VERSION 5.8 ;
BUSBITCHARS "[]" ;
DIVIDERCHAR "/" ;
UNITS
    DATABASE MICRONS 1000 ;
END UNITS

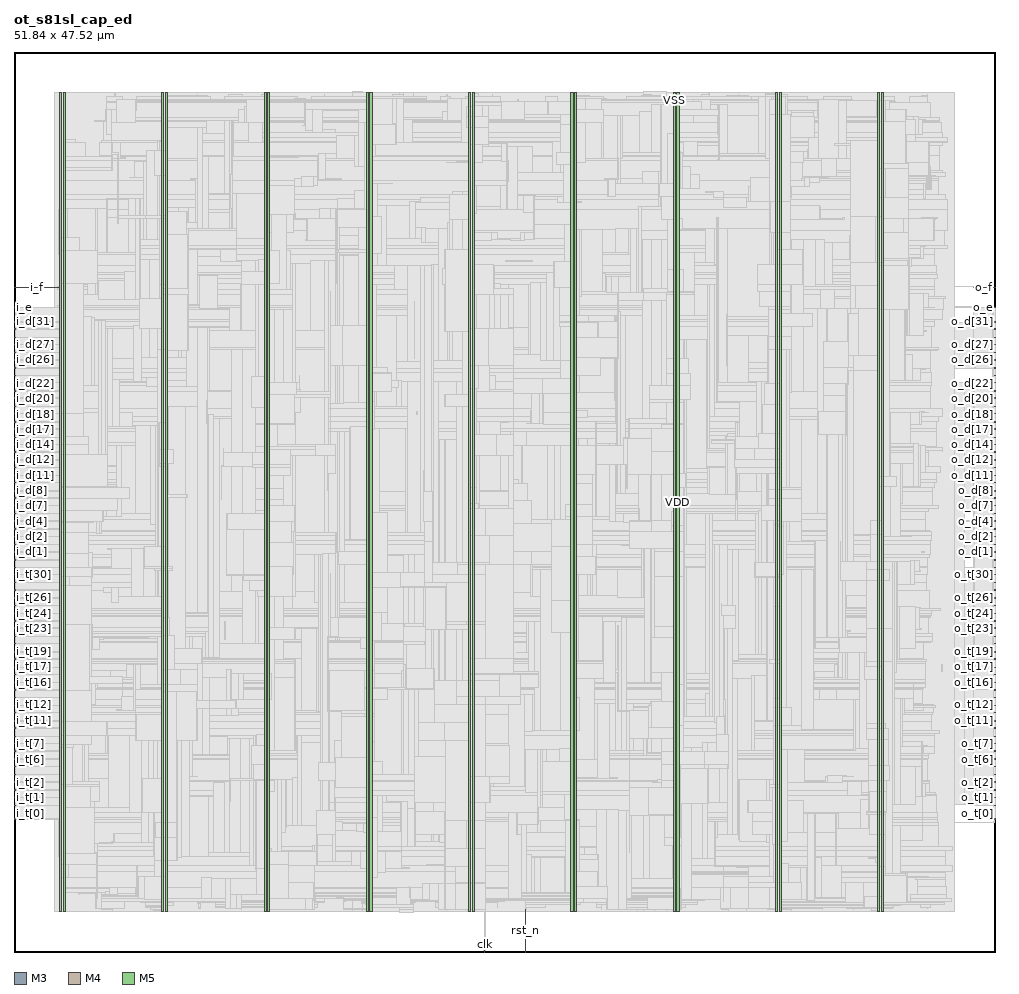
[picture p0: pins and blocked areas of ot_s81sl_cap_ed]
MACRO ot_s81sl_cap_ed
  FOREIGN ot_s81sl_cap_ed 0 0 ;
  CLASS BLOCK ;
  SIZE 51.84 BY 47.52 ;
  PIN clk
    DIRECTION INPUT ;
    USE SIGNAL ;
    PORT
      LAYER M3 ;
        RECT  24.84 0 24.858 0.038 ;
    END
    PORT
      LAYER M3 ;
        RECT  24.84 0.012 24.858 0.125 ;
    END
  END clk
  PIN i_d[0]
    DIRECTION INPUT ;
    USE SIGNAL ;
    PORT
      LAYER M4 ;
        RECT  0 20.688 0.084 20.712 ;
    END
  END i_d[0]
  PIN i_d[10]
    DIRECTION INPUT ;
    USE SIGNAL ;
    PORT
      LAYER M4 ;
        RECT  0 24.768 0.084 24.792 ;
    END
  END i_d[10]
  PIN i_d[11]
    DIRECTION INPUT ;
    USE SIGNAL ;
    PORT
      LAYER M4 ;
        RECT  0 25.152 0.084 25.176 ;
    END
  END i_d[11]
  PIN i_d[12]
    DIRECTION INPUT ;
    USE SIGNAL ;
    PORT
      LAYER M4 ;
        RECT  0 25.584 0.084 25.608 ;
    END
  END i_d[12]
  PIN i_d[13]
    DIRECTION INPUT ;
    USE SIGNAL ;
    PORT
      LAYER M4 ;
        RECT  0 25.968 0.084 25.992 ;
    END
  END i_d[13]
  PIN i_d[14]
    DIRECTION INPUT ;
    USE SIGNAL ;
    PORT
      LAYER M4 ;
        RECT  0 26.4 0.084 26.424 ;
    END
  END i_d[14]
  PIN i_d[15]
    DIRECTION INPUT ;
    USE SIGNAL ;
    PORT
      LAYER M4 ;
        RECT  0 26.784 0.084 26.808 ;
    END
  END i_d[15]
  PIN i_d[16]
    DIRECTION INPUT ;
    USE SIGNAL ;
    PORT
      LAYER M4 ;
        RECT  0 27.168 0.084 27.192 ;
    END
  END i_d[16]
  PIN i_d[17]
    DIRECTION INPUT ;
    USE SIGNAL ;
    PORT
      LAYER M4 ;
        RECT  0 27.6 0.084 27.624 ;
    END
  END i_d[17]
  PIN i_d[18]
    DIRECTION INPUT ;
    USE SIGNAL ;
    PORT
      LAYER M4 ;
        RECT  0 27.984 0.084 28.008 ;
    END
  END i_d[18]
  PIN i_d[19]
    DIRECTION INPUT ;
    USE SIGNAL ;
    PORT
      LAYER M4 ;
        RECT  0 28.416 0.084 28.44 ;
    END
  END i_d[19]
  PIN i_d[1]
    DIRECTION INPUT ;
    USE SIGNAL ;
    PORT
      LAYER M4 ;
        RECT  0 21.12 0.084 21.144 ;
    END
  END i_d[1]
  PIN i_d[20]
    DIRECTION INPUT ;
    USE SIGNAL ;
    PORT
      LAYER M4 ;
        RECT  0 28.8 0.084 28.824 ;
    END
  END i_d[20]
  PIN i_d[21]
    DIRECTION INPUT ;
    USE SIGNAL ;
    PORT
      LAYER M4 ;
        RECT  0 29.232 0.084 29.256 ;
    END
  END i_d[21]
  PIN i_d[22]
    DIRECTION INPUT ;
    USE SIGNAL ;
    PORT
      LAYER M4 ;
        RECT  0 29.616 0.084 29.64 ;
    END
  END i_d[22]
  PIN i_d[23]
    DIRECTION INPUT ;
    USE SIGNAL ;
    PORT
      LAYER M4 ;
        RECT  0 30.048 0.084 30.072 ;
    END
  END i_d[23]
  PIN i_d[24]
    DIRECTION INPUT ;
    USE SIGNAL ;
    PORT
      LAYER M4 ;
        RECT  0 30.432 0.084 30.456 ;
    END
  END i_d[24]
  PIN i_d[25]
    DIRECTION INPUT ;
    USE SIGNAL ;
    PORT
      LAYER M4 ;
        RECT  0 30.816 0.084 30.84 ;
    END
  END i_d[25]
  PIN i_d[26]
    DIRECTION INPUT ;
    USE SIGNAL ;
    PORT
      LAYER M4 ;
        RECT  0 31.248 0.084 31.272 ;
    END
  END i_d[26]
  PIN i_d[27]
    DIRECTION INPUT ;
    USE SIGNAL ;
    PORT
      LAYER M4 ;
        RECT  0 31.632 0.084 31.656 ;
    END
  END i_d[27]
  PIN i_d[28]
    DIRECTION INPUT ;
    USE SIGNAL ;
    PORT
      LAYER M4 ;
        RECT  0 32.064 0.084 32.088 ;
    END
  END i_d[28]
  PIN i_d[29]
    DIRECTION INPUT ;
    USE SIGNAL ;
    PORT
      LAYER M4 ;
        RECT  0 32.448 0.084 32.472 ;
    END
  END i_d[29]
  PIN i_d[2]
    DIRECTION INPUT ;
    USE SIGNAL ;
    PORT
      LAYER M4 ;
        RECT  0 21.504 0.084 21.528 ;
    END
  END i_d[2]
  PIN i_d[30]
    DIRECTION INPUT ;
    USE SIGNAL ;
    PORT
      LAYER M4 ;
        RECT  0 32.88 0.084 32.904 ;
    END
  END i_d[30]
  PIN i_d[31]
    DIRECTION INPUT ;
    USE SIGNAL ;
    PORT
      LAYER M4 ;
        RECT  0 33.264 0.084 33.288 ;
    END
  END i_d[31]
  PIN i_d[3]
    DIRECTION INPUT ;
    USE SIGNAL ;
    PORT
      LAYER M4 ;
        RECT  0 21.936 0.084 21.96 ;
    END
  END i_d[3]
  PIN i_d[4]
    DIRECTION INPUT ;
    USE SIGNAL ;
    PORT
      LAYER M4 ;
        RECT  0 22.32 0.084 22.344 ;
    END
  END i_d[4]
  PIN i_d[5]
    DIRECTION INPUT ;
    USE SIGNAL ;
    PORT
      LAYER M4 ;
        RECT  0 22.752 0.084 22.776 ;
    END
  END i_d[5]
  PIN i_d[6]
    DIRECTION INPUT ;
    USE SIGNAL ;
    PORT
      LAYER M4 ;
        RECT  0 23.136 0.084 23.16 ;
    END
  END i_d[6]
  PIN i_d[7]
    DIRECTION INPUT ;
    USE SIGNAL ;
    PORT
      LAYER M4 ;
        RECT  0 23.568 0.084 23.592 ;
    END
  END i_d[7]
  PIN i_d[8]
    DIRECTION INPUT ;
    USE SIGNAL ;
    PORT
      LAYER M4 ;
        RECT  0 23.952 0.084 23.976 ;
    END
  END i_d[8]
  PIN i_d[9]
    DIRECTION INPUT ;
    USE SIGNAL ;
    PORT
      LAYER M4 ;
        RECT  0 24.336 0.084 24.36 ;
    END
  END i_d[9]
  PIN i_e
    DIRECTION INPUT ;
    USE SIGNAL ;
    PORT
      LAYER M4 ;
        RECT  0 34.032 0.084 34.056 ;
    END
  END i_e
  PIN i_f
    DIRECTION INPUT ;
    USE SIGNAL ;
    PORT
      LAYER M4 ;
        RECT  0 35.088 0.084 35.112 ;
    END
    PORT
      LAYER M4 ;
        RECT  0.06 35.088 2.408 35.112 ;
    END
  END i_f
  PIN i_t[0]
    DIRECTION INPUT ;
    USE SIGNAL ;
    PORT
      LAYER M4 ;
        RECT  0 7.728 0.084 7.752 ;
    END
  END i_t[0]
  PIN i_t[10]
    DIRECTION INPUT ;
    USE SIGNAL ;
    PORT
      LAYER M4 ;
        RECT  0 11.808 0.084 11.832 ;
    END
  END i_t[10]
  PIN i_t[11]
    DIRECTION INPUT ;
    USE SIGNAL ;
    PORT
      LAYER M4 ;
        RECT  0 12.192 0.084 12.216 ;
    END
  END i_t[11]
  PIN i_t[12]
    DIRECTION INPUT ;
    USE SIGNAL ;
    PORT
      LAYER M4 ;
        RECT  0 12.624 0.084 12.648 ;
    END
  END i_t[12]
  PIN i_t[13]
    DIRECTION INPUT ;
    USE SIGNAL ;
    PORT
      LAYER M4 ;
        RECT  0 13.008 0.084 13.032 ;
    END
  END i_t[13]
  PIN i_t[14]
    DIRECTION INPUT ;
    USE SIGNAL ;
    PORT
      LAYER M4 ;
        RECT  0 13.44 0.084 13.464 ;
    END
  END i_t[14]
  PIN i_t[15]
    DIRECTION INPUT ;
    USE SIGNAL ;
    PORT
      LAYER M4 ;
        RECT  0 13.824 0.084 13.848 ;
    END
  END i_t[15]
  PIN i_t[16]
    DIRECTION INPUT ;
    USE SIGNAL ;
    PORT
      LAYER M4 ;
        RECT  0 14.208 0.084 14.232 ;
    END
  END i_t[16]
  PIN i_t[17]
    DIRECTION INPUT ;
    USE SIGNAL ;
    PORT
      LAYER M4 ;
        RECT  0 14.64 0.084 14.664 ;
    END
  END i_t[17]
  PIN i_t[18]
    DIRECTION INPUT ;
    USE SIGNAL ;
    PORT
      LAYER M4 ;
        RECT  0 15.024 0.084 15.048 ;
    END
  END i_t[18]
  PIN i_t[19]
    DIRECTION INPUT ;
    USE SIGNAL ;
    PORT
      LAYER M4 ;
        RECT  0 15.456 0.084 15.48 ;
    END
  END i_t[19]
  PIN i_t[1]
    DIRECTION INPUT ;
    USE SIGNAL ;
    PORT
      LAYER M4 ;
        RECT  0 8.16 0.084 8.184 ;
    END
  END i_t[1]
  PIN i_t[20]
    DIRECTION INPUT ;
    USE SIGNAL ;
    PORT
      LAYER M4 ;
        RECT  0 15.84 0.084 15.864 ;
    END
  END i_t[20]
  PIN i_t[21]
    DIRECTION INPUT ;
    USE SIGNAL ;
    PORT
      LAYER M4 ;
        RECT  0 16.272 0.084 16.296 ;
    END
  END i_t[21]
  PIN i_t[22]
    DIRECTION INPUT ;
    USE SIGNAL ;
    PORT
      LAYER M4 ;
        RECT  0 16.656 0.084 16.68 ;
    END
  END i_t[22]
  PIN i_t[23]
    DIRECTION INPUT ;
    USE SIGNAL ;
    PORT
      LAYER M4 ;
        RECT  0 17.088 0.084 17.112 ;
    END
  END i_t[23]
  PIN i_t[24]
    DIRECTION INPUT ;
    USE SIGNAL ;
    PORT
      LAYER M4 ;
        RECT  0 17.472 0.084 17.496 ;
    END
  END i_t[24]
  PIN i_t[25]
    DIRECTION INPUT ;
    USE SIGNAL ;
    PORT
      LAYER M4 ;
        RECT  0 17.856 0.084 17.88 ;
    END
  END i_t[25]
  PIN i_t[26]
    DIRECTION INPUT ;
    USE SIGNAL ;
    PORT
      LAYER M4 ;
        RECT  0 18.288 0.084 18.312 ;
    END
  END i_t[26]
  PIN i_t[27]
    DIRECTION INPUT ;
    USE SIGNAL ;
    PORT
      LAYER M4 ;
        RECT  0 18.672 0.084 18.696 ;
    END
  END i_t[27]
  PIN i_t[28]
    DIRECTION INPUT ;
    USE SIGNAL ;
    PORT
      LAYER M4 ;
        RECT  0 19.104 0.084 19.128 ;
    END
  END i_t[28]
  PIN i_t[29]
    DIRECTION INPUT ;
    USE SIGNAL ;
    PORT
      LAYER M4 ;
        RECT  0 19.488 0.084 19.512 ;
    END
  END i_t[29]
  PIN i_t[2]
    DIRECTION INPUT ;
    USE SIGNAL ;
    PORT
      LAYER M4 ;
        RECT  0 8.544 0.084 8.568 ;
    END
  END i_t[2]
  PIN i_t[30]
    DIRECTION INPUT ;
    USE SIGNAL ;
    PORT
      LAYER M4 ;
        RECT  0 19.92 0.084 19.944 ;
    END
  END i_t[30]
  PIN i_t[31]
    DIRECTION INPUT ;
    USE SIGNAL ;
    PORT
      LAYER M4 ;
        RECT  0 20.304 0.084 20.328 ;
    END
  END i_t[31]
  PIN i_t[3]
    DIRECTION INPUT ;
    USE SIGNAL ;
    PORT
      LAYER M4 ;
        RECT  0 8.976 0.084 9 ;
    END
  END i_t[3]
  PIN i_t[4]
    DIRECTION INPUT ;
    USE SIGNAL ;
    PORT
      LAYER M4 ;
        RECT  0 9.36 0.084 9.384 ;
    END
  END i_t[4]
  PIN i_t[5]
    DIRECTION INPUT ;
    USE SIGNAL ;
    PORT
      LAYER M4 ;
        RECT  0 9.792 0.084 9.816 ;
    END
  END i_t[5]
  PIN i_t[6]
    DIRECTION INPUT ;
    USE SIGNAL ;
    PORT
      LAYER M4 ;
        RECT  0 10.176 0.084 10.2 ;
    END
  END i_t[6]
  PIN i_t[7]
    DIRECTION INPUT ;
    USE SIGNAL ;
    PORT
      LAYER M4 ;
        RECT  0 10.608 0.084 10.632 ;
    END
  END i_t[7]
  PIN i_t[8]
    DIRECTION INPUT ;
    USE SIGNAL ;
    PORT
      LAYER M4 ;
        RECT  0 10.992 0.084 11.016 ;
    END
  END i_t[8]
  PIN i_t[9]
    DIRECTION INPUT ;
    USE SIGNAL ;
    PORT
      LAYER M4 ;
        RECT  0 11.376 0.084 11.4 ;
    END
  END i_t[9]
  PIN i_v
    DIRECTION INPUT ;
    USE SIGNAL ;
    PORT
      LAYER M4 ;
        RECT  0 7.008 0.084 7.032 ;
    END
  END i_v
  PIN o_d[0]
    DIRECTION OUTPUT ;
    USE SIGNAL ;
    PORT
      LAYER M4 ;
        RECT  51.756 20.688 51.84 20.712 ;
    END
  END o_d[0]
  PIN o_d[10]
    DIRECTION OUTPUT ;
    USE SIGNAL ;
    PORT
      LAYER M4 ;
        RECT  51.756 24.768 51.84 24.792 ;
    END
  END o_d[10]
  PIN o_d[11]
    DIRECTION OUTPUT ;
    USE SIGNAL ;
    PORT
      LAYER M4 ;
        RECT  51.756 25.152 51.84 25.176 ;
    END
  END o_d[11]
  PIN o_d[12]
    DIRECTION OUTPUT ;
    USE SIGNAL ;
    PORT
      LAYER M4 ;
        RECT  51.756 25.584 51.84 25.608 ;
    END
  END o_d[12]
  PIN o_d[13]
    DIRECTION OUTPUT ;
    USE SIGNAL ;
    PORT
      LAYER M4 ;
        RECT  51.756 25.968 51.84 25.992 ;
    END
  END o_d[13]
  PIN o_d[14]
    DIRECTION OUTPUT ;
    USE SIGNAL ;
    PORT
      LAYER M4 ;
        RECT  51.756 26.4 51.84 26.424 ;
    END
  END o_d[14]
  PIN o_d[15]
    DIRECTION OUTPUT ;
    USE SIGNAL ;
    PORT
      LAYER M4 ;
        RECT  51.756 26.784 51.84 26.808 ;
    END
  END o_d[15]
  PIN o_d[16]
    DIRECTION OUTPUT ;
    USE SIGNAL ;
    PORT
      LAYER M4 ;
        RECT  51.756 27.168 51.84 27.192 ;
    END
  END o_d[16]
  PIN o_d[17]
    DIRECTION OUTPUT ;
    USE SIGNAL ;
    PORT
      LAYER M4 ;
        RECT  51.756 27.6 51.84 27.624 ;
    END
  END o_d[17]
  PIN o_d[18]
    DIRECTION OUTPUT ;
    USE SIGNAL ;
    PORT
      LAYER M4 ;
        RECT  51.756 27.984 51.84 28.008 ;
    END
  END o_d[18]
  PIN o_d[19]
    DIRECTION OUTPUT ;
    USE SIGNAL ;
    PORT
      LAYER M4 ;
        RECT  51.756 28.416 51.84 28.44 ;
    END
  END o_d[19]
  PIN o_d[1]
    DIRECTION OUTPUT ;
    USE SIGNAL ;
    PORT
      LAYER M4 ;
        RECT  51.756 21.12 51.84 21.144 ;
    END
  END o_d[1]
  PIN o_d[20]
    DIRECTION OUTPUT ;
    USE SIGNAL ;
    PORT
      LAYER M4 ;
        RECT  51.756 28.8 51.84 28.824 ;
    END
  END o_d[20]
  PIN o_d[21]
    DIRECTION OUTPUT ;
    USE SIGNAL ;
    PORT
      LAYER M4 ;
        RECT  51.756 29.232 51.84 29.256 ;
    END
  END o_d[21]
  PIN o_d[22]
    DIRECTION OUTPUT ;
    USE SIGNAL ;
    PORT
      LAYER M4 ;
        RECT  51.756 29.616 51.84 29.64 ;
    END
  END o_d[22]
  PIN o_d[23]
    DIRECTION OUTPUT ;
    USE SIGNAL ;
    PORT
      LAYER M4 ;
        RECT  51.756 30.048 51.84 30.072 ;
    END
  END o_d[23]
  PIN o_d[24]
    DIRECTION OUTPUT ;
    USE SIGNAL ;
    PORT
      LAYER M4 ;
        RECT  51.756 30.432 51.84 30.456 ;
    END
  END o_d[24]
  PIN o_d[25]
    DIRECTION OUTPUT ;
    USE SIGNAL ;
    PORT
      LAYER M4 ;
        RECT  51.756 30.816 51.84 30.84 ;
    END
  END o_d[25]
  PIN o_d[26]
    DIRECTION OUTPUT ;
    USE SIGNAL ;
    PORT
      LAYER M4 ;
        RECT  51.756 31.248 51.84 31.272 ;
    END
  END o_d[26]
  PIN o_d[27]
    DIRECTION OUTPUT ;
    USE SIGNAL ;
    PORT
      LAYER M4 ;
        RECT  51.756 31.632 51.84 31.656 ;
    END
  END o_d[27]
  PIN o_d[28]
    DIRECTION OUTPUT ;
    USE SIGNAL ;
    PORT
      LAYER M4 ;
        RECT  51.756 32.064 51.84 32.088 ;
    END
  END o_d[28]
  PIN o_d[29]
    DIRECTION OUTPUT ;
    USE SIGNAL ;
    PORT
      LAYER M4 ;
        RECT  51.756 32.448 51.84 32.472 ;
    END
  END o_d[29]
  PIN o_d[2]
    DIRECTION OUTPUT ;
    USE SIGNAL ;
    PORT
      LAYER M4 ;
        RECT  51.756 21.504 51.84 21.528 ;
    END
  END o_d[2]
  PIN o_d[30]
    DIRECTION OUTPUT ;
    USE SIGNAL ;
    PORT
      LAYER M4 ;
        RECT  51.756 32.88 51.84 32.904 ;
    END
  END o_d[30]
  PIN o_d[31]
    DIRECTION OUTPUT ;
    USE SIGNAL ;
    PORT
      LAYER M4 ;
        RECT  51.756 33.264 51.84 33.288 ;
    END
  END o_d[31]
  PIN o_d[3]
    DIRECTION OUTPUT ;
    USE SIGNAL ;
    PORT
      LAYER M4 ;
        RECT  51.756 21.936 51.84 21.96 ;
    END
  END o_d[3]
  PIN o_d[4]
    DIRECTION OUTPUT ;
    USE SIGNAL ;
    PORT
      LAYER M4 ;
        RECT  51.756 22.32 51.84 22.344 ;
    END
  END o_d[4]
  PIN o_d[5]
    DIRECTION OUTPUT ;
    USE SIGNAL ;
    PORT
      LAYER M4 ;
        RECT  51.756 22.752 51.84 22.776 ;
    END
  END o_d[5]
  PIN o_d[6]
    DIRECTION OUTPUT ;
    USE SIGNAL ;
    PORT
      LAYER M4 ;
        RECT  51.756 23.136 51.84 23.16 ;
    END
  END o_d[6]
  PIN o_d[7]
    DIRECTION OUTPUT ;
    USE SIGNAL ;
    PORT
      LAYER M4 ;
        RECT  51.756 23.568 51.84 23.592 ;
    END
  END o_d[7]
  PIN o_d[8]
    DIRECTION OUTPUT ;
    USE SIGNAL ;
    PORT
      LAYER M4 ;
        RECT  51.756 23.952 51.84 23.976 ;
    END
  END o_d[8]
  PIN o_d[9]
    DIRECTION OUTPUT ;
    USE SIGNAL ;
    PORT
      LAYER M4 ;
        RECT  51.756 24.336 51.84 24.36 ;
    END
  END o_d[9]
  PIN o_e
    DIRECTION OUTPUT ;
    USE SIGNAL ;
    PORT
      LAYER M4 ;
        RECT  51.756 34.032 51.84 34.056 ;
    END
  END o_e
  PIN o_f
    DIRECTION OUTPUT ;
    USE SIGNAL ;
    PORT
      LAYER M4 ;
        RECT  51.756 35.088 51.84 35.112 ;
    END
    PORT
      LAYER M4 ;
        RECT  50.677 35.088 51.804 35.112 ;
    END
  END o_f
  PIN o_t[0]
    DIRECTION OUTPUT ;
    USE SIGNAL ;
    PORT
      LAYER M4 ;
        RECT  51.756 7.728 51.84 7.752 ;
    END
  END o_t[0]
  PIN o_t[10]
    DIRECTION OUTPUT ;
    USE SIGNAL ;
    PORT
      LAYER M4 ;
        RECT  51.756 11.808 51.84 11.832 ;
    END
  END o_t[10]
  PIN o_t[11]
    DIRECTION OUTPUT ;
    USE SIGNAL ;
    PORT
      LAYER M4 ;
        RECT  51.756 12.192 51.84 12.216 ;
    END
  END o_t[11]
  PIN o_t[12]
    DIRECTION OUTPUT ;
    USE SIGNAL ;
    PORT
      LAYER M4 ;
        RECT  51.756 12.624 51.84 12.648 ;
    END
  END o_t[12]
  PIN o_t[13]
    DIRECTION OUTPUT ;
    USE SIGNAL ;
    PORT
      LAYER M4 ;
        RECT  51.756 13.008 51.84 13.032 ;
    END
  END o_t[13]
  PIN o_t[14]
    DIRECTION OUTPUT ;
    USE SIGNAL ;
    PORT
      LAYER M4 ;
        RECT  51.756 13.44 51.84 13.464 ;
    END
  END o_t[14]
  PIN o_t[15]
    DIRECTION OUTPUT ;
    USE SIGNAL ;
    PORT
      LAYER M4 ;
        RECT  51.756 13.824 51.84 13.848 ;
    END
  END o_t[15]
  PIN o_t[16]
    DIRECTION OUTPUT ;
    USE SIGNAL ;
    PORT
      LAYER M4 ;
        RECT  51.756 14.208 51.84 14.232 ;
    END
  END o_t[16]
  PIN o_t[17]
    DIRECTION OUTPUT ;
    USE SIGNAL ;
    PORT
      LAYER M4 ;
        RECT  51.756 14.64 51.84 14.664 ;
    END
  END o_t[17]
  PIN o_t[18]
    DIRECTION OUTPUT ;
    USE SIGNAL ;
    PORT
      LAYER M4 ;
        RECT  51.756 15.024 51.84 15.048 ;
    END
  END o_t[18]
  PIN o_t[19]
    DIRECTION OUTPUT ;
    USE SIGNAL ;
    PORT
      LAYER M4 ;
        RECT  51.756 15.456 51.84 15.48 ;
    END
  END o_t[19]
  PIN o_t[1]
    DIRECTION OUTPUT ;
    USE SIGNAL ;
    PORT
      LAYER M4 ;
        RECT  51.756 8.16 51.84 8.184 ;
    END
  END o_t[1]
  PIN o_t[20]
    DIRECTION OUTPUT ;
    USE SIGNAL ;
    PORT
      LAYER M4 ;
        RECT  51.756 15.84 51.84 15.864 ;
    END
  END o_t[20]
  PIN o_t[21]
    DIRECTION OUTPUT ;
    USE SIGNAL ;
    PORT
      LAYER M4 ;
        RECT  51.756 16.272 51.84 16.296 ;
    END
  END o_t[21]
  PIN o_t[22]
    DIRECTION OUTPUT ;
    USE SIGNAL ;
    PORT
      LAYER M4 ;
        RECT  51.756 16.656 51.84 16.68 ;
    END
  END o_t[22]
  PIN o_t[23]
    DIRECTION OUTPUT ;
    USE SIGNAL ;
    PORT
      LAYER M4 ;
        RECT  51.756 17.088 51.84 17.112 ;
    END
  END o_t[23]
  PIN o_t[24]
    DIRECTION OUTPUT ;
    USE SIGNAL ;
    PORT
      LAYER M4 ;
        RECT  51.756 17.472 51.84 17.496 ;
    END
  END o_t[24]
  PIN o_t[25]
    DIRECTION OUTPUT ;
    USE SIGNAL ;
    PORT
      LAYER M4 ;
        RECT  51.756 17.856 51.84 17.88 ;
    END
  END o_t[25]
  PIN o_t[26]
    DIRECTION OUTPUT ;
    USE SIGNAL ;
    PORT
      LAYER M4 ;
        RECT  51.756 18.288 51.84 18.312 ;
    END
  END o_t[26]
  PIN o_t[27]
    DIRECTION OUTPUT ;
    USE SIGNAL ;
    PORT
      LAYER M4 ;
        RECT  51.756 18.672 51.84 18.696 ;
    END
  END o_t[27]
  PIN o_t[28]
    DIRECTION OUTPUT ;
    USE SIGNAL ;
    PORT
      LAYER M4 ;
        RECT  51.756 19.104 51.84 19.128 ;
    END
  END o_t[28]
  PIN o_t[29]
    DIRECTION OUTPUT ;
    USE SIGNAL ;
    PORT
      LAYER M4 ;
        RECT  51.756 19.488 51.84 19.512 ;
    END
  END o_t[29]
  PIN o_t[2]
    DIRECTION OUTPUT ;
    USE SIGNAL ;
    PORT
      LAYER M4 ;
        RECT  51.756 8.544 51.84 8.568 ;
    END
  END o_t[2]
  PIN o_t[30]
    DIRECTION OUTPUT ;
    USE SIGNAL ;
    PORT
      LAYER M4 ;
        RECT  51.756 19.92 51.84 19.944 ;
    END
  END o_t[30]
  PIN o_t[31]
    DIRECTION OUTPUT ;
    USE SIGNAL ;
    PORT
      LAYER M4 ;
        RECT  51.756 20.304 51.84 20.328 ;
    END
  END o_t[31]
  PIN o_t[3]
    DIRECTION OUTPUT ;
    USE SIGNAL ;
    PORT
      LAYER M4 ;
        RECT  51.756 8.976 51.84 9 ;
    END
  END o_t[3]
  PIN o_t[4]
    DIRECTION OUTPUT ;
    USE SIGNAL ;
    PORT
      LAYER M4 ;
        RECT  51.756 9.36 51.84 9.384 ;
    END
  END o_t[4]
  PIN o_t[5]
    DIRECTION OUTPUT ;
    USE SIGNAL ;
    PORT
      LAYER M4 ;
        RECT  51.756 9.792 51.84 9.816 ;
    END
  END o_t[5]
  PIN o_t[6]
    DIRECTION OUTPUT ;
    USE SIGNAL ;
    PORT
      LAYER M4 ;
        RECT  51.756 10.176 51.84 10.2 ;
    END
  END o_t[6]
  PIN o_t[7]
    DIRECTION OUTPUT ;
    USE SIGNAL ;
    PORT
      LAYER M4 ;
        RECT  51.756 10.608 51.84 10.632 ;
    END
  END o_t[7]
  PIN o_t[8]
    DIRECTION OUTPUT ;
    USE SIGNAL ;
    PORT
      LAYER M4 ;
        RECT  51.756 10.992 51.84 11.016 ;
    END
  END o_t[8]
  PIN o_t[9]
    DIRECTION OUTPUT ;
    USE SIGNAL ;
    PORT
      LAYER M4 ;
        RECT  51.756 11.376 51.84 11.4 ;
    END
  END o_t[9]
  PIN o_v
    DIRECTION OUTPUT ;
    USE SIGNAL ;
    PORT
      LAYER M4 ;
        RECT  51.756 7.008 51.84 7.032 ;
    END
  END o_v
  PIN rst_n
    DIRECTION INPUT ;
    USE SIGNAL ;
    PORT
      LAYER M3 ;
        RECT  27 0 27.018 0.038 ;
    END
    PORT
      LAYER M3 ;
        RECT  27 0.012 27.018 2.227 ;
    END
  END rst_n
  PIN VDD
    DIRECTION INOUT ;
    USE POWER ;
    PORT
      LAYER M5 ;
        RECT  45.792 2.151 45.912 45.369 ;
        RECT  40.392 2.151 40.512 45.369 ;
        RECT  34.992 2.151 35.112 45.369 ;
        RECT  29.592 2.151 29.712 45.369 ;
        RECT  24.192 2.151 24.312 45.369 ;
        RECT  18.792 2.151 18.912 45.369 ;
        RECT  13.392 2.151 13.512 45.369 ;
        RECT  7.992 2.151 8.112 45.369 ;
        RECT  2.592 2.151 2.712 45.369 ;
    END
  END VDD
  PIN VSS
    DIRECTION INOUT ;
    USE GROUND ;
    PORT
      LAYER M5 ;
        RECT  45.6 2.137 45.72 45.383 ;
        RECT  40.2 2.137 40.32 45.383 ;
        RECT  34.8 2.137 34.92 45.383 ;
        RECT  29.4 2.137 29.52 45.383 ;
        RECT  24 2.137 24.12 45.383 ;
        RECT  18.6 2.137 18.72 45.383 ;
        RECT  13.2 2.137 13.32 45.383 ;
        RECT  7.8 2.137 7.92 45.383 ;
        RECT  2.4 2.137 2.52 45.383 ;
    END
  END VSS
  # OT_OBS_CLOSED layer=M5 d_um=1.536 added=241
  OBS
    LAYER RVTN ;
     RECT  2.16 2.16 49.68 2.295 ;
     RECT  2.16 2.565 49.68 2.835 ;
     RECT  2.16 3.105 49.68 3.375 ;
     RECT  2.16 3.645 49.68 3.915 ;
     RECT  2.16 4.185 49.68 4.455 ;
     RECT  2.16 4.725 49.68 4.995 ;
     RECT  2.16 5.265 49.68 5.535 ;
     RECT  2.16 5.805 49.68 6.075 ;
     RECT  2.16 6.345 49.68 6.615 ;
     RECT  2.16 6.885 49.68 7.155 ;
     RECT  2.16 7.425 49.68 7.695 ;
     RECT  2.16 7.965 49.68 8.235 ;
     RECT  2.16 8.505 49.68 8.775 ;
     RECT  2.16 9.045 49.68 9.315 ;
     RECT  2.16 9.585 49.68 9.855 ;
     RECT  2.16 10.125 49.68 10.395 ;
     RECT  2.16 10.665 49.68 10.935 ;
     RECT  2.16 11.205 49.68 11.475 ;
     RECT  2.16 11.745 49.68 12.015 ;
     RECT  2.16 12.285 49.68 12.555 ;
     RECT  2.16 12.825 49.68 13.095 ;
     RECT  2.16 13.365 49.68 13.635 ;
     RECT  2.16 13.905 49.68 14.175 ;
     RECT  2.16 14.445 49.68 14.715 ;
     RECT  2.16 14.985 49.68 15.255 ;
     RECT  2.16 15.525 49.68 15.795 ;
     RECT  2.16 16.065 49.68 16.335 ;
     RECT  2.16 16.605 49.68 16.875 ;
     RECT  2.16 17.145 49.68 17.415 ;
     RECT  2.16 17.685 49.68 17.955 ;
     RECT  2.16 18.225 49.68 18.495 ;
     RECT  2.16 18.765 49.68 19.035 ;
     RECT  2.16 19.305 49.68 19.575 ;
     RECT  2.16 19.845 49.68 20.115 ;
     RECT  2.16 20.385 49.68 20.655 ;
     RECT  2.16 20.925 49.68 21.195 ;
     RECT  2.16 21.465 49.68 21.735 ;
     RECT  2.16 22.005 49.68 22.275 ;
     RECT  2.16 22.545 49.68 22.815 ;
     RECT  2.16 23.085 49.68 23.355 ;
     RECT  2.16 23.625 49.68 23.895 ;
     RECT  2.16 24.165 49.68 24.435 ;
     RECT  2.16 24.705 49.68 24.975 ;
     RECT  2.16 25.245 49.68 25.515 ;
     RECT  2.16 25.785 49.68 26.055 ;
     RECT  2.16 26.325 49.68 26.595 ;
     RECT  2.16 26.865 49.68 27.135 ;
     RECT  2.16 27.405 49.68 27.675 ;
     RECT  2.16 27.945 49.68 28.215 ;
     RECT  2.16 28.485 49.68 28.755 ;
     RECT  2.16 29.025 49.68 29.295 ;
     RECT  2.16 29.565 49.68 29.835 ;
     RECT  2.16 30.105 49.68 30.375 ;
     RECT  2.16 30.645 49.68 30.915 ;
     RECT  2.16 31.185 49.68 31.455 ;
     RECT  2.16 31.725 49.68 31.995 ;
     RECT  2.16 32.265 49.68 32.535 ;
     RECT  2.16 32.805 49.68 33.075 ;
     RECT  2.16 33.345 49.68 33.615 ;
     RECT  2.16 33.885 49.68 34.155 ;
     RECT  2.16 34.425 49.68 34.695 ;
     RECT  2.16 34.965 49.68 35.235 ;
     RECT  2.16 35.505 49.68 35.775 ;
     RECT  2.16 36.045 49.68 36.315 ;
     RECT  2.16 36.585 49.68 36.855 ;
     RECT  2.16 37.125 49.68 37.395 ;
     RECT  2.16 37.665 49.68 37.935 ;
     RECT  2.16 38.205 49.68 38.475 ;
     RECT  2.16 38.745 49.68 39.015 ;
     RECT  2.16 39.285 49.68 39.555 ;
     RECT  2.16 39.825 49.68 40.095 ;
     RECT  2.16 40.365 49.68 40.635 ;
     RECT  2.16 40.905 49.68 41.175 ;
     RECT  2.16 41.445 49.68 41.715 ;
     RECT  2.16 41.985 49.68 42.255 ;
     RECT  2.16 42.525 49.68 42.795 ;
     RECT  2.16 43.065 49.68 43.335 ;
     RECT  2.16 43.605 49.68 43.875 ;
     RECT  2.16 44.145 49.68 44.415 ;
     RECT  2.16 44.685 49.68 44.955 ;
     RECT  2.16 45.225 49.68 45.36 ;
    LAYER RVTP ;
     RECT  2.16 2.295 49.68 2.565 ;
     RECT  2.16 2.835 49.68 3.105 ;
     RECT  2.16 3.375 49.68 3.645 ;
     RECT  2.16 3.915 49.68 4.185 ;
     RECT  2.16 4.455 49.68 4.725 ;
     RECT  2.16 4.995 49.68 5.265 ;
     RECT  2.16 5.535 49.68 5.805 ;
     RECT  2.16 6.075 49.68 6.345 ;
     RECT  2.16 6.615 49.68 6.885 ;
     RECT  2.16 7.155 49.68 7.425 ;
     RECT  2.16 7.695 49.68 7.965 ;
     RECT  2.16 8.235 49.68 8.505 ;
     RECT  2.16 8.775 49.68 9.045 ;
     RECT  2.16 9.315 49.68 9.585 ;
     RECT  2.16 9.855 49.68 10.125 ;
     RECT  2.16 10.395 49.68 10.665 ;
     RECT  2.16 10.935 49.68 11.205 ;
     RECT  2.16 11.475 49.68 11.745 ;
     RECT  2.16 12.015 49.68 12.285 ;
     RECT  2.16 12.555 49.68 12.825 ;
     RECT  2.16 13.095 49.68 13.365 ;
     RECT  2.16 13.635 49.68 13.905 ;
     RECT  2.16 14.175 49.68 14.445 ;
     RECT  2.16 14.715 49.68 14.985 ;
     RECT  2.16 15.255 49.68 15.525 ;
     RECT  2.16 15.795 49.68 16.065 ;
     RECT  2.16 16.335 49.68 16.605 ;
     RECT  2.16 16.875 49.68 17.145 ;
     RECT  2.16 17.415 49.68 17.685 ;
     RECT  2.16 17.955 49.68 18.225 ;
     RECT  2.16 18.495 49.68 18.765 ;
     RECT  2.16 19.035 49.68 19.305 ;
     RECT  2.16 19.575 49.68 19.845 ;
     RECT  2.16 20.115 49.68 20.385 ;
     RECT  2.16 20.655 49.68 20.925 ;
     RECT  2.16 21.195 49.68 21.465 ;
     RECT  2.16 21.735 49.68 22.005 ;
     RECT  2.16 22.275 49.68 22.545 ;
     RECT  2.16 22.815 49.68 23.085 ;
     RECT  2.16 23.355 49.68 23.625 ;
     RECT  2.16 23.895 49.68 24.165 ;
     RECT  2.16 24.435 49.68 24.705 ;
     RECT  2.16 24.975 49.68 25.245 ;
     RECT  2.16 25.515 49.68 25.785 ;
     RECT  2.16 26.055 49.68 26.325 ;
     RECT  2.16 26.595 49.68 26.865 ;
     RECT  2.16 27.135 49.68 27.405 ;
     RECT  2.16 27.675 49.68 27.945 ;
     RECT  2.16 28.215 49.68 28.485 ;
     RECT  2.16 28.755 49.68 29.025 ;
     RECT  2.16 29.295 49.68 29.565 ;
     RECT  2.16 29.835 49.68 30.105 ;
     RECT  2.16 30.375 49.68 30.645 ;
     RECT  2.16 30.915 49.68 31.185 ;
     RECT  2.16 31.455 49.68 31.725 ;
     RECT  2.16 31.995 49.68 32.265 ;
     RECT  2.16 32.535 49.68 32.805 ;
     RECT  2.16 33.075 49.68 33.345 ;
     RECT  2.16 33.615 49.68 33.885 ;
     RECT  2.16 34.155 49.68 34.425 ;
     RECT  2.16 34.695 49.68 34.965 ;
     RECT  2.16 35.235 49.68 35.505 ;
     RECT  2.16 35.775 49.68 36.045 ;
     RECT  2.16 36.315 49.68 36.585 ;
     RECT  2.16 36.855 49.68 37.125 ;
     RECT  2.16 37.395 49.68 37.665 ;
     RECT  2.16 37.935 49.68 38.205 ;
     RECT  2.16 38.475 49.68 38.745 ;
     RECT  2.16 39.015 49.68 39.285 ;
     RECT  2.16 39.555 49.68 39.825 ;
     RECT  2.16 40.095 49.68 40.365 ;
     RECT  2.16 40.635 49.68 40.905 ;
     RECT  2.16 41.175 49.68 41.445 ;
     RECT  2.16 41.715 49.68 41.985 ;
     RECT  2.16 42.255 49.68 42.525 ;
     RECT  2.16 42.795 49.68 43.065 ;
     RECT  2.16 43.335 49.68 43.605 ;
     RECT  2.16 43.875 49.68 44.145 ;
     RECT  2.16 44.415 49.68 44.685 ;
     RECT  2.16 44.955 49.68 45.225 ;
    LAYER M1 ;
     RECT  2.16 2.151 49.68 45.369 ;
    LAYER M2 ;
     RECT  2.16 2.151 17.851 45.369 ;
     RECT  17.851 2.151 18.383 45.414 ;
     RECT  18.383 2.151 20.335 45.369 ;
     RECT  20.335 2.106 21.119 45.369 ;
     RECT  21.119 2.151 33.223 45.369 ;
     RECT  33.223 2.151 34.475 45.414 ;
     RECT  34.475 2.151 49.68 45.369 ;
     RECT  49.68 7.776 50.207 30.06 ;
     RECT  50.207 7.776 50.675 19.944 ;
     RECT  50.675 7.938 50.711 19.944 ;
     RECT  50.207 20.826 50.711 22.464 ;
     RECT  50.207 23.256 50.711 30.06 ;
     RECT  49.68 30.816 50.711 33.264 ;
     RECT  49.68 34.056 50.711 34.074 ;
     RECT  49.68 35.136 50.711 35.154 ;
     RECT  50.711 7.938 50.747 7.956 ;
     RECT  50.711 16.506 50.747 17.064 ;
     RECT  50.711 19.476 50.747 19.494 ;
     RECT  50.711 21.636 50.747 21.924 ;
     RECT  50.711 25.686 50.747 25.974 ;
     RECT  50.711 28.386 50.747 28.404 ;
     RECT  50.711 30.816 50.747 31.914 ;
     RECT  49.68 6.822 51.755 6.84 ;
     RECT  50.711 10.296 51.755 10.314 ;
     RECT  50.711 14.346 51.755 15.354 ;
     RECT  50.747 21.636 51.755 21.654 ;
     RECT  50.747 25.686 51.755 25.704 ;
     RECT  50.711 26.766 51.755 26.784 ;
     RECT  50.711 29.736 51.755 29.754 ;
     RECT  50.747 30.816 51.755 31.374 ;
     RECT  50.711 32.976 51.755 32.994 ;
    LAYER M3 ;
     RECT  7.815 2.143 7.905 2.191 ;
     RECT  24.015 2.143 24.105 2.191 ;
     RECT  45.615 2.143 45.705 2.191 ;
     RECT  7.38 2.191 7.905 2.227 ;
     RECT  20.34 2.101 20.358 2.227 ;
     RECT  21.096 2.101 21.114 2.227 ;
     RECT  22.824 2.191 22.842 2.227 ;
     RECT  23.94 2.191 24.105 2.227 ;
     RECT  32.904 2.191 32.922 2.227 ;
     RECT  40.215 2.143 40.305 2.227 ;
     RECT  22.824 2.227 23.094 2.251 ;
     RECT  23.94 2.227 24.498 2.251 ;
     RECT  32.328 2.227 32.922 2.251 ;
     RECT  33.804 2.191 33.822 2.251 ;
     RECT  5.184 2.191 5.202 2.263 ;
     RECT  37.728 2.191 37.746 2.263 ;
     RECT  39.78 2.227 40.305 2.263 ;
     RECT  41.04 2.191 41.058 2.263 ;
     RECT  4.608 2.263 5.202 2.299 ;
     RECT  11.988 2.227 12.006 2.299 ;
     RECT  38.664 2.191 38.682 2.299 ;
     RECT  39.78 2.263 41.058 2.299 ;
     RECT  42.696 2.263 42.714 2.299 ;
     RECT  44.316 2.263 44.334 2.299 ;
     RECT  45.288 2.191 45.705 2.299 ;
     RECT  7.2 2.227 7.905 2.335 ;
     RECT  9.756 2.299 9.846 2.335 ;
     RECT  11.16 2.299 12.006 2.335 ;
     RECT  15.84 2.251 15.858 2.335 ;
     RECT  22.428 2.251 24.498 2.335 ;
     RECT  39.78 2.299 42.714 2.335 ;
     RECT  43.956 2.299 46.386 2.335 ;
     RECT  7.02 2.335 7.974 2.371 ;
     RECT  10.656 2.335 12.186 2.371 ;
     RECT  13.215 2.143 13.305 2.371 ;
     RECT  14.184 2.227 14.202 2.371 ;
     RECT  15.732 2.335 15.858 2.371 ;
     RECT  18.615 2.143 18.705 2.371 ;
     RECT  20.34 2.227 21.114 2.371 ;
     RECT  27 2.227 27.054 2.371 ;
     RECT  30.996 2.263 31.014 2.371 ;
     RECT  32.328 2.251 33.822 2.371 ;
     RECT  34.815 2.143 34.905 2.371 ;
     RECT  37.332 2.263 37.746 2.371 ;
     RECT  38.484 2.299 38.682 2.371 ;
     RECT  39.78 2.335 42.93 2.371 ;
     RECT  43.74 2.335 46.386 2.371 ;
     RECT  48.24 2.299 48.258 2.371 ;
     RECT  2.415 2.143 2.505 2.413 ;
     RECT  6.948 2.371 7.974 2.413 ;
     RECT  10.656 2.371 13.305 2.413 ;
     RECT  14.184 2.371 14.994 2.413 ;
     RECT  29.415 2.143 29.505 2.413 ;
     RECT  6.948 2.413 8.097 2.461 ;
     RECT  39.78 2.371 46.458 2.461 ;
     RECT  10.656 2.413 14.994 2.497 ;
     RECT  15.732 2.371 16.038 2.497 ;
     RECT  18.615 2.371 21.114 2.497 ;
     RECT  27 2.371 28.062 2.497 ;
     RECT  29.415 2.413 29.697 2.497 ;
     RECT  39.78 2.461 46.782 2.497 ;
     RECT  47.88 2.371 48.402 2.497 ;
     RECT  27 2.497 28.242 2.533 ;
     RECT  29.088 2.497 29.934 2.533 ;
     RECT  30.78 2.371 31.014 2.533 ;
     RECT  32.148 2.371 35.478 2.533 ;
     RECT  39.78 2.497 49.014 2.533 ;
     RECT  9.72 2.335 9.846 2.569 ;
     RECT  18.576 2.497 21.114 2.569 ;
     RECT  6.948 2.461 8.442 2.605 ;
     RECT  9.684 2.569 9.846 2.605 ;
     RECT  10.656 2.497 16.038 2.605 ;
     RECT  18.36 2.569 21.114 2.605 ;
     RECT  22.248 2.335 24.498 2.605 ;
     RECT  25.524 2.371 25.542 2.605 ;
     RECT  27 2.533 29.934 2.605 ;
     RECT  30.78 2.533 31.266 2.605 ;
     RECT  32.148 2.533 36.09 2.605 ;
     RECT  37.332 2.371 38.79 2.605 ;
     RECT  39.78 2.533 49.122 2.605 ;
     RECT  4.32 2.299 5.85 2.641 ;
     RECT  6.696 2.605 8.442 2.641 ;
     RECT  9.684 2.605 16.398 2.641 ;
     RECT  17.388 2.251 17.406 2.641 ;
     RECT  18.36 2.605 21.222 2.641 ;
     RECT  22.248 2.605 25.542 2.641 ;
     RECT  37.332 2.605 49.122 2.641 ;
     RECT  37.332 2.641 49.482 2.669 ;
     RECT  17.388 2.641 17.478 2.731 ;
     RECT  18.36 2.641 25.902 2.731 ;
     RECT  27 2.605 36.09 2.731 ;
     RECT  17.388 2.731 36.45 2.779 ;
     RECT  37.332 2.669 46.566 2.803 ;
     RECT  47.34 2.669 49.482 2.831 ;
     RECT  4.32 2.641 16.398 2.839 ;
     RECT  17.388 2.779 36.522 2.839 ;
     RECT  4.32 2.839 36.522 2.911 ;
     RECT  4.284 2.911 36.522 3.001 ;
     RECT  37.26 2.803 46.566 3.001 ;
     RECT  47.34 2.831 49.23 3.029 ;
     RECT  3.456 3.037 3.474 3.073 ;
     RECT  4.284 3.001 46.566 3.073 ;
     RECT  3.456 3.073 46.566 3.109 ;
     RECT  2.415 2.413 2.697 3.145 ;
     RECT  3.42 3.109 46.566 3.145 ;
     RECT  2.415 3.145 46.566 3.335 ;
     RECT  2.415 3.335 42.498 3.407 ;
     RECT  47.7 3.029 49.23 3.443 ;
     RECT  47.7 3.443 49.158 3.811 ;
     RECT  43.416 3.335 46.566 3.955 ;
     RECT  47.592 3.811 49.158 3.955 ;
     RECT  32.508 3.407 42.498 4.081 ;
     RECT  32.508 4.081 42.606 4.171 ;
     RECT  32.508 4.171 42.678 4.189 ;
     RECT  43.416 3.955 49.158 4.189 ;
     RECT  2.415 3.407 31.698 4.225 ;
     RECT  32.508 4.189 49.158 4.225 ;
     RECT  2.415 4.225 49.158 4.261 ;
     RECT  2.415 4.261 49.554 4.559 ;
     RECT  2.415 4.559 49.158 5.035 ;
     RECT  2.376 5.035 49.158 5.341 ;
     RECT  2.376 5.341 49.554 5.567 ;
     RECT  2.376 5.567 48.834 6.845 ;
     RECT  2.376 6.845 48.762 7.003 ;
     RECT  51.732 6.817 51.75 7.037 ;
     RECT  2.304 7.003 48.762 7.115 ;
     RECT  2.376 7.115 48.762 7.349 ;
     RECT  50.652 7.723 50.67 7.799 ;
     RECT  50.724 7.933 50.742 8.189 ;
     RECT  2.415 7.349 48.69 8.267 ;
     RECT  44.748 8.267 48.69 8.303 ;
     RECT  44.748 8.303 48.654 8.429 ;
     RECT  2.415 8.267 44.01 8.539 ;
     RECT  2.304 8.539 44.01 9.005 ;
     RECT  2.415 9.005 44.01 9.013 ;
     RECT  44.748 8.429 48.33 9.013 ;
     RECT  2.415 9.013 48.33 9.077 ;
     RECT  50.688 8.539 50.706 9.821 ;
     RECT  2.415 9.077 48.258 10.171 ;
     RECT  2.304 10.171 48.258 10.201 ;
     RECT  51.732 10.171 51.75 10.319 ;
     RECT  2.304 10.201 48.294 10.355 ;
     RECT  2.415 10.355 48.294 10.471 ;
     RECT  0.108 11.227 0.126 11.405 ;
     RECT  2.415 10.471 48.582 11.435 ;
     RECT  38.628 11.435 48.582 11.551 ;
     RECT  38.628 11.551 48.87 11.669 ;
     RECT  2.415 11.435 37.854 11.803 ;
     RECT  2.304 11.803 37.854 12.181 ;
     RECT  38.628 11.669 48.438 12.181 ;
     RECT  2.304 12.181 48.438 12.523 ;
     RECT  2.304 12.523 48.474 12.631 ;
     RECT  2.304 12.631 48.546 12.901 ;
     RECT  2.304 12.901 48.654 13.019 ;
     RECT  43.308 13.019 48.546 13.055 ;
     RECT  43.38 13.055 48.546 13.091 ;
     RECT  43.38 13.091 47.97 13.127 ;
     RECT  2.304 13.019 42.534 13.325 ;
     RECT  0.108 13.435 0.126 13.613 ;
     RECT  2.376 13.325 42.534 13.837 ;
     RECT  50.688 10.561 50.706 13.853 ;
     RECT  2.376 13.837 42.57 13.873 ;
     RECT  43.416 13.127 47.97 13.873 ;
     RECT  2.376 13.873 47.97 13.909 ;
     RECT  2.376 13.909 48.006 13.945 ;
     RECT  2.376 13.945 48.114 14.203 ;
     RECT  2.304 14.203 48.114 14.215 ;
     RECT  2.304 14.215 48.15 14.369 ;
     RECT  2.304 14.369 48.114 14.405 ;
     RECT  48.996 14.791 49.014 15.179 ;
     RECT  2.376 14.405 48.114 15.245 ;
     RECT  2.412 15.245 48.114 15.331 ;
     RECT  51.732 14.203 51.75 15.359 ;
     RECT  2.412 15.331 48.186 15.449 ;
     RECT  2.412 15.449 48.042 15.485 ;
     RECT  50.724 15.151 50.742 15.485 ;
     RECT  50.688 15.835 50.706 16.301 ;
     RECT  2.415 15.485 48.042 16.339 ;
     RECT  2.415 16.339 48.366 16.375 ;
     RECT  2.415 16.375 48.474 16.651 ;
     RECT  2.304 16.651 48.474 16.799 ;
     RECT  2.304 16.799 48.294 16.835 ;
     RECT  2.304 16.835 42.714 16.907 ;
     RECT  2.304 16.907 42.642 17.117 ;
     RECT  50.724 16.501 50.742 17.117 ;
     RECT  43.56 16.835 48.294 17.653 ;
     RECT  2.376 17.117 42.642 17.689 ;
     RECT  43.56 17.653 48.402 17.689 ;
     RECT  2.376 17.689 48.402 17.761 ;
     RECT  2.376 17.761 48.438 17.851 ;
     RECT  2.304 17.851 48.438 18.031 ;
     RECT  2.304 18.031 48.906 18.149 ;
     RECT  2.304 18.149 48.33 19.103 ;
     RECT  50.688 17.467 50.706 19.471 ;
     RECT  50.688 19.471 50.742 19.517 ;
     RECT  2.304 19.103 48.186 19.535 ;
     RECT  2.412 19.535 48.186 19.921 ;
     RECT  0.108 19.819 0.126 19.949 ;
     RECT  50.688 19.517 50.706 19.949 ;
     RECT  2.412 19.921 48.222 20.299 ;
     RECT  50.184 20.191 50.202 20.333 ;
     RECT  2.34 20.299 48.222 20.345 ;
     RECT  2.415 20.345 48.222 20.821 ;
     RECT  2.415 20.821 48.33 21.001 ;
     RECT  50.688 20.683 50.706 21.155 ;
     RECT  2.415 21.001 48.366 21.499 ;
     RECT  51.732 21.499 51.75 21.659 ;
     RECT  2.304 21.499 48.366 21.703 ;
     RECT  2.304 21.703 48.438 21.965 ;
     RECT  50.724 21.901 50.742 21.965 ;
     RECT  2.415 21.965 48.438 22.199 ;
     RECT  2.415 22.199 48.33 22.235 ;
     RECT  50.688 22.315 50.706 22.711 ;
     RECT  50.184 22.711 50.706 22.781 ;
     RECT  2.415 22.235 48.114 22.843 ;
     RECT  2.376 22.843 48.114 23.251 ;
     RECT  2.376 23.251 48.294 23.431 ;
     RECT  2.376 23.431 48.798 23.549 ;
     RECT  2.376 23.549 48.474 23.557 ;
     RECT  2.34 23.557 48.474 24.331 ;
     RECT  2.304 24.331 48.474 24.511 ;
     RECT  2.304 24.511 48.618 24.781 ;
     RECT  2.304 24.781 48.69 24.935 ;
     RECT  50.688 22.781 50.706 25.181 ;
     RECT  2.376 24.935 48.69 25.321 ;
     RECT  2.376 25.321 48.906 25.619 ;
     RECT  51.732 25.579 51.75 25.709 ;
     RECT  50.724 25.951 50.742 25.997 ;
     RECT  0.108 25.963 0.126 26.093 ;
     RECT  2.376 25.619 48.294 26.395 ;
     RECT  2.304 26.395 48.294 26.491 ;
     RECT  49.032 26.401 49.05 26.491 ;
     RECT  2.304 26.491 49.05 26.663 ;
     RECT  2.304 26.663 48.726 26.699 ;
     RECT  51.732 26.761 51.75 26.813 ;
     RECT  2.304 26.699 26.226 26.897 ;
     RECT  2.34 26.897 26.226 27.481 ;
     RECT  27.036 26.699 48.726 27.481 ;
     RECT  2.34 27.481 48.726 27.635 ;
     RECT  2.376 27.635 48.726 28.021 ;
     RECT  2.376 28.021 48.834 28.291 ;
     RECT  50.688 26.395 50.706 28.381 ;
     RECT  50.688 28.381 50.742 28.445 ;
     RECT  2.376 28.291 49.014 28.679 ;
     RECT  50.688 28.445 50.706 29.261 ;
     RECT  2.415 28.679 48.402 29.611 ;
     RECT  2.304 29.611 48.402 29.911 ;
     RECT  2.304 29.911 48.438 30.077 ;
     RECT  50.688 30.037 50.706 30.077 ;
     RECT  2.415 30.077 48.438 30.605 ;
     RECT  2.415 30.605 48.402 30.811 ;
     RECT  51.732 29.611 51.75 30.811 ;
     RECT  51.696 30.811 51.75 31.109 ;
     RECT  0.108 31.147 0.126 31.277 ;
     RECT  51.732 31.109 51.75 31.379 ;
     RECT  50.688 31.621 50.706 31.661 ;
     RECT  2.304 30.811 48.402 31.765 ;
     RECT  2.304 31.765 48.762 31.801 ;
     RECT  2.304 31.801 48.834 31.919 ;
     RECT  50.724 31.891 50.742 32.093 ;
     RECT  50.688 32.431 50.706 32.477 ;
     RECT  51.732 32.875 51.75 32.999 ;
     RECT  2.304 31.919 48.438 33.043 ;
     RECT  2.304 33.043 48.582 33.293 ;
     RECT  50.688 33.241 50.706 33.293 ;
     RECT  2.415 33.293 48.582 33.421 ;
     RECT  2.415 33.421 49.014 33.917 ;
     RECT  43.344 33.917 49.014 33.925 ;
     RECT  2.415 33.917 35.55 34.027 ;
     RECT  50.688 34.027 50.706 34.079 ;
     RECT  2.304 34.027 35.55 34.115 ;
     RECT  43.344 33.925 49.086 34.501 ;
     RECT  43.344 34.501 49.194 34.619 ;
     RECT  2.415 34.115 35.55 34.699 ;
     RECT  36.396 33.917 42.606 34.699 ;
     RECT  2.415 34.699 42.606 35.005 ;
     RECT  43.344 34.619 48.582 35.005 ;
     RECT  2.304 35.005 48.582 35.117 ;
     RECT  2.415 35.117 48.582 35.159 ;
     RECT  50.688 35.083 50.706 35.159 ;
     RECT  3.42 35.159 48.582 35.581 ;
     RECT  3.42 35.581 48.762 35.771 ;
     RECT  2.415 35.159 2.697 35.899 ;
     RECT  3.42 35.771 48.69 35.899 ;
     RECT  2.415 35.899 48.69 36.239 ;
     RECT  2.415 36.239 48.618 36.823 ;
     RECT  2.376 36.823 48.618 37.129 ;
     RECT  2.376 37.129 49.266 37.319 ;
     RECT  2.376 37.319 49.122 38.101 ;
     RECT  2.376 38.101 49.302 39.209 ;
     RECT  2.415 39.209 49.302 39.749 ;
     RECT  2.415 39.749 49.194 40.019 ;
     RECT  2.415 40.019 48.798 40.739 ;
     RECT  41.58 40.739 48.798 40.865 ;
     RECT  41.616 40.865 48.798 40.937 ;
     RECT  43.452 40.937 48.798 40.945 ;
     RECT  43.452 40.945 49.194 41.135 ;
     RECT  43.452 41.135 49.014 41.279 ;
     RECT  2.415 40.739 40.806 41.791 ;
     RECT  41.616 40.937 42.642 41.791 ;
     RECT  2.415 41.791 42.642 42.017 ;
     RECT  4.5 42.017 42.642 42.053 ;
     RECT  36.108 42.053 42.642 42.061 ;
     RECT  43.452 41.279 48.87 42.061 ;
     RECT  36.108 42.061 48.87 42.565 ;
     RECT  36.108 42.565 49.014 42.727 ;
     RECT  2.415 42.017 3.762 42.755 ;
     RECT  4.5 42.053 35.334 42.755 ;
     RECT  13.104 42.755 35.334 42.799 ;
     RECT  36.108 42.727 49.266 42.799 ;
     RECT  4.644 42.755 12.366 42.827 ;
     RECT  2.415 42.755 3.258 42.899 ;
     RECT  13.104 42.799 49.266 42.989 ;
     RECT  13.104 42.989 49.014 43.259 ;
     RECT  13.104 43.259 48.978 43.799 ;
     RECT  4.716 42.827 12.366 43.843 ;
     RECT  13.104 43.799 48.87 43.843 ;
     RECT  4.284 43.843 48.87 43.901 ;
     RECT  4.86 43.901 48.87 44.069 ;
     RECT  4.86 44.069 48.402 44.879 ;
     RECT  4.86 44.879 28.674 44.909 ;
     RECT  4.86 44.909 26.622 44.915 ;
     RECT  27.504 44.909 28.674 44.915 ;
     RECT  45.504 44.879 46.53 44.915 ;
     RECT  6.444 44.915 23.058 44.951 ;
     RECT  29.415 44.879 44.55 44.957 ;
     RECT  45.504 44.915 46.494 44.957 ;
     RECT  29.415 44.957 44.262 44.987 ;
     RECT  6.444 44.951 21.798 45.023 ;
     RECT  26.604 44.915 26.622 45.023 ;
     RECT  39.672 44.987 44.262 45.023 ;
     RECT  29.415 44.987 31.302 45.059 ;
     RECT  2.415 42.899 2.697 45.107 ;
     RECT  4.86 44.915 5.706 45.149 ;
     RECT  6.444 45.023 10.35 45.149 ;
     RECT  11.124 45.023 14.958 45.149 ;
     RECT  15.732 45.023 21.798 45.149 ;
     RECT  22.536 44.951 23.058 45.149 ;
     RECT  23.832 44.915 25.686 45.149 ;
     RECT  28.08 44.915 28.674 45.149 ;
     RECT  29.415 45.059 31.122 45.149 ;
     RECT  32.328 44.987 38.934 45.149 ;
     RECT  39.672 45.023 41.922 45.149 ;
     RECT  42.732 45.023 44.226 45.149 ;
     RECT  45.615 44.957 46.494 45.149 ;
     RECT  47.268 44.879 48.258 45.149 ;
     RECT  6.444 45.149 6.462 45.185 ;
     RECT  11.34 45.149 14.274 45.185 ;
     RECT  16.38 45.149 21.222 45.185 ;
     RECT  22.536 45.149 22.878 45.185 ;
     RECT  24.015 45.149 25.686 45.185 ;
     RECT  29.415 45.149 30.978 45.185 ;
     RECT  32.328 45.149 32.346 45.185 ;
     RECT  33.12 45.149 38.79 45.185 ;
     RECT  42.732 45.149 42.75 45.185 ;
     RECT  43.488 45.149 43.506 45.185 ;
     RECT  7.815 45.149 10.206 45.197 ;
     RECT  37.62 45.185 38.79 45.197 ;
     RECT  7.815 45.197 8.622 45.221 ;
     RECT  29.415 45.185 30.402 45.221 ;
     RECT  33.12 45.185 34.905 45.221 ;
     RECT  37.62 45.197 38.25 45.221 ;
     RECT  47.916 45.149 48.258 45.221 ;
     RECT  9.684 45.197 9.702 45.257 ;
     RECT  11.34 45.185 12.042 45.257 ;
     RECT  16.38 45.185 16.398 45.257 ;
     RECT  19.98 45.185 20.574 45.257 ;
     RECT  25.272 45.185 25.29 45.257 ;
     RECT  36.324 45.185 36.702 45.257 ;
     RECT  48.24 45.221 48.258 45.257 ;
     RECT  12.024 45.257 12.042 45.293 ;
     RECT  13.068 45.185 13.305 45.293 ;
     RECT  22.86 45.185 22.878 45.293 ;
     RECT  33.228 45.221 33.678 45.293 ;
     RECT  36.612 45.257 36.702 45.293 ;
     RECT  38.232 45.221 38.25 45.293 ;
     RECT  39.672 45.149 40.842 45.293 ;
     RECT  5.328 45.149 5.346 45.329 ;
     RECT  20.556 45.257 20.574 45.329 ;
     RECT  24.015 45.185 24.534 45.329 ;
     RECT  36.684 45.293 36.702 45.329 ;
     RECT  39.672 45.293 40.305 45.329 ;
     RECT  2.415 45.107 2.505 45.377 ;
     RECT  7.815 45.221 7.905 45.377 ;
     RECT  13.215 45.293 13.305 45.377 ;
     RECT  17.856 45.185 18.705 45.377 ;
     RECT  24.015 45.329 24.105 45.377 ;
     RECT  29.415 45.221 29.505 45.377 ;
     RECT  34.452 45.221 34.905 45.377 ;
     RECT  40.215 45.329 40.305 45.377 ;
     RECT  45.615 45.149 45.705 45.377 ;
     RECT  17.856 45.377 18.378 45.419 ;
     RECT  33.228 45.293 33.246 45.419 ;
     RECT  34.452 45.377 34.47 45.419 ;
    LAYER M4 ;
     RECT  2.365 5.04 2.408 5.064 ;
     RECT  0.084 7.008 2.408 7.032 ;
     RECT  0.06 7.032 2.408 7.728 ;
     RECT  0.084 7.728 2.408 7.752 ;
     RECT  0.06 7.752 2.408 8.16 ;
     RECT  0.084 8.16 2.408 8.184 ;
     RECT  0.06 8.184 2.408 8.544 ;
     RECT  0.084 8.544 2.408 8.568 ;
     RECT  0.06 8.568 2.408 8.976 ;
     RECT  0.084 8.976 2.408 9 ;
     RECT  0.06 9 2.408 9.36 ;
     RECT  0.084 9.36 2.408 9.384 ;
     RECT  0.06 9.384 2.408 9.792 ;
     RECT  0.084 9.792 2.408 9.816 ;
     RECT  0.06 9.816 2.408 10.176 ;
     RECT  0.084 10.176 2.408 10.2 ;
     RECT  0.06 10.2 2.408 10.608 ;
     RECT  0.084 10.608 2.408 10.632 ;
     RECT  0.06 10.632 2.408 10.992 ;
     RECT  0.084 10.992 2.408 11.016 ;
     RECT  0.06 11.016 2.408 11.376 ;
     RECT  0.084 11.376 2.408 11.4 ;
     RECT  0.06 11.4 2.408 11.808 ;
     RECT  0.084 11.808 2.408 11.832 ;
     RECT  0.06 11.832 2.408 12.192 ;
     RECT  0.084 12.192 2.408 12.216 ;
     RECT  0.06 12.216 2.408 12.624 ;
     RECT  0.084 12.624 2.408 12.648 ;
     RECT  0.06 12.648 2.408 13.008 ;
     RECT  0.084 13.008 2.408 13.032 ;
     RECT  0.06 13.032 2.408 13.44 ;
     RECT  0.084 13.44 2.408 13.464 ;
     RECT  0.06 13.464 2.408 13.824 ;
     RECT  0.084 13.824 2.408 13.848 ;
     RECT  0.06 13.848 2.408 14.208 ;
     RECT  0.084 14.208 2.408 14.232 ;
     RECT  0.06 14.232 2.408 14.64 ;
     RECT  0.084 14.64 2.408 14.664 ;
     RECT  0.06 14.664 2.408 15.024 ;
     RECT  0.084 15.024 2.408 15.048 ;
     RECT  0.06 15.048 2.408 15.456 ;
     RECT  0.084 15.456 2.408 15.48 ;
     RECT  0.06 15.48 2.408 15.84 ;
     RECT  0.084 15.84 2.408 15.864 ;
     RECT  0.06 15.864 2.408 16.272 ;
     RECT  0.084 16.272 2.408 16.296 ;
     RECT  0.06 16.296 2.408 16.656 ;
     RECT  0.084 16.656 2.408 16.68 ;
     RECT  0.06 16.68 2.408 17.088 ;
     RECT  0.084 17.088 2.408 17.112 ;
     RECT  0.06 17.112 2.408 17.472 ;
     RECT  0.084 17.472 2.408 17.496 ;
     RECT  0.06 17.496 2.408 17.856 ;
     RECT  0.084 17.856 2.408 17.88 ;
     RECT  0.06 17.88 2.408 18.288 ;
     RECT  0.084 18.288 2.408 18.312 ;
     RECT  0.06 18.312 2.408 18.672 ;
     RECT  0.084 18.672 2.408 18.696 ;
     RECT  0.06 18.696 2.408 19.104 ;
     RECT  0.084 19.104 2.408 19.128 ;
     RECT  0.06 19.128 2.408 19.488 ;
     RECT  0.084 19.488 2.408 19.512 ;
     RECT  0.06 19.512 2.408 19.92 ;
     RECT  0.084 19.92 2.408 19.944 ;
     RECT  0.06 19.944 2.408 20.304 ;
     RECT  0.084 20.304 2.408 20.328 ;
     RECT  0.06 20.328 2.408 20.688 ;
     RECT  0.084 20.688 2.408 20.712 ;
     RECT  0.06 20.712 2.408 21.12 ;
     RECT  0.084 21.12 2.408 21.144 ;
     RECT  0.06 21.144 2.408 21.504 ;
     RECT  0.084 21.504 2.408 21.528 ;
     RECT  0.06 21.528 2.408 21.936 ;
     RECT  0.084 21.936 2.408 21.96 ;
     RECT  0.06 21.96 2.408 22.32 ;
     RECT  0.084 22.32 2.408 22.344 ;
     RECT  0.06 22.344 2.408 22.752 ;
     RECT  0.084 22.752 2.408 22.776 ;
     RECT  0.06 22.776 2.408 23.136 ;
     RECT  0.084 23.136 2.408 23.16 ;
     RECT  0.06 23.16 2.408 23.568 ;
     RECT  0.084 23.568 2.408 23.592 ;
     RECT  0.06 23.592 2.408 23.952 ;
     RECT  0.084 23.952 2.408 23.976 ;
     RECT  0.06 23.976 2.408 24.336 ;
     RECT  0.084 24.336 2.408 24.36 ;
     RECT  0.06 24.36 2.408 24.768 ;
     RECT  0.084 24.768 2.408 24.792 ;
     RECT  0.06 24.792 2.408 25.152 ;
     RECT  0.084 25.152 2.408 25.176 ;
     RECT  0.06 25.176 2.408 25.584 ;
     RECT  0.084 25.584 2.408 25.608 ;
     RECT  0.06 25.608 2.408 25.968 ;
     RECT  0.084 25.968 2.408 25.992 ;
     RECT  0.06 25.992 2.408 26.4 ;
     RECT  0.084 26.4 2.408 26.424 ;
     RECT  0.06 26.424 2.408 26.784 ;
     RECT  0.084 26.784 2.408 26.808 ;
     RECT  0.06 26.808 2.408 27.168 ;
     RECT  0.084 27.168 2.408 27.192 ;
     RECT  0.06 27.192 2.408 27.6 ;
     RECT  0.084 27.6 2.408 27.624 ;
     RECT  0.06 27.624 2.408 27.984 ;
     RECT  0.084 27.984 2.408 28.008 ;
     RECT  0.06 28.008 2.408 28.416 ;
     RECT  0.084 28.416 2.408 28.44 ;
     RECT  0.06 28.44 2.408 28.8 ;
     RECT  0.084 28.8 2.408 28.824 ;
     RECT  0.06 28.824 2.408 29.232 ;
     RECT  0.084 29.232 2.408 29.256 ;
     RECT  0.06 29.256 2.408 29.616 ;
     RECT  0.084 29.616 2.408 29.64 ;
     RECT  0.06 29.64 2.408 30.048 ;
     RECT  0.084 30.048 2.408 30.072 ;
     RECT  0.06 30.072 2.408 30.432 ;
     RECT  0.084 30.432 2.408 30.456 ;
     RECT  0.06 30.456 2.408 30.816 ;
     RECT  0.084 30.816 2.408 30.84 ;
     RECT  0.06 30.84 2.408 31.248 ;
     RECT  0.084 31.248 2.408 31.272 ;
     RECT  0.06 31.272 2.408 31.632 ;
     RECT  0.084 31.632 2.408 31.656 ;
     RECT  0.06 31.656 2.408 32.064 ;
     RECT  0.084 32.064 2.408 32.088 ;
     RECT  0.06 32.088 2.408 32.448 ;
     RECT  0.084 32.448 2.408 32.472 ;
     RECT  0.06 32.472 2.408 32.88 ;
     RECT  0.084 32.88 2.408 32.904 ;
     RECT  0.06 32.904 2.408 33.264 ;
     RECT  0.084 33.264 2.408 33.288 ;
     RECT  0.06 33.288 2.408 34.032 ;
     RECT  0.084 34.032 2.408 34.056 ;
     RECT  2.408 2.148 2.512 45.372 ;
     RECT  2.512 2.418 2.704 45.102 ;
     RECT  2.704 17.472 2.765 17.496 ;
     RECT  2.704 22.176 2.819 39.24 ;
     RECT  2.819 35.232 2.837 39.24 ;
     RECT  2.704 3.936 2.867 5.064 ;
     RECT  2.867 4.56 2.905 5.064 ;
     RECT  2.704 7.2 2.981 16.296 ;
     RECT  2.704 19.344 3.004 21.144 ;
     RECT  2.819 22.176 3.059 34.2 ;
     RECT  3.004 19.776 3.089 21.144 ;
     RECT  2.981 12.768 3.155 16.296 ;
     RECT  3.059 26.064 3.197 34.2 ;
     RECT  3.197 26.064 3.449 33.576 ;
     RECT  2.981 7.2 3.629 11.784 ;
     RECT  2.905 4.896 3.697 5.064 ;
     RECT  3.155 13.056 3.733 16.296 ;
     RECT  3.629 7.2 3.737 11.448 ;
     RECT  2.837 35.232 3.877 35.448 ;
     RECT  3.737 7.632 3.953 11.448 ;
     RECT  3.733 13.056 3.973 16.536 ;
     RECT  3.973 13.056 4.019 17.304 ;
     RECT  4.019 15.84 4.029 17.304 ;
     RECT  3.449 29.904 4.097 33.576 ;
     RECT  4.029 15.888 4.115 17.304 ;
     RECT  4.115 15.984 4.133 17.304 ;
     RECT  3.089 19.776 4.169 21.096 ;
     RECT  3.697 4.896 4.205 5.736 ;
     RECT  4.097 29.904 4.241 33.48 ;
     RECT  4.019 13.056 4.313 14.52 ;
     RECT  3.877 34.704 4.316 35.448 ;
     RECT  2.837 36.624 4.316 39.24 ;
     RECT  4.309 2.304 4.345 2.328 ;
     RECT  4.345 2.304 4.357 2.856 ;
     RECT  3.059 22.176 4.381 24.504 ;
     RECT  4.205 5.232 4.403 5.736 ;
     RECT  4.316 34.704 4.403 39.24 ;
     RECT  4.313 13.92 4.421 14.52 ;
     RECT  3.449 26.208 4.453 28.488 ;
     RECT  4.241 29.904 4.453 33.336 ;
     RECT  4.403 34.704 4.453 35.448 ;
     RECT  4.403 5.712 4.525 5.736 ;
     RECT  4.381 22.08 4.525 24.504 ;
     RECT  4.133 15.984 4.529 16.584 ;
     RECT  4.453 26.208 4.597 33.336 ;
     RECT  4.525 22.08 4.601 24.552 ;
     RECT  4.357 2.304 4.637 3.144 ;
     RECT  4.529 16.512 4.706 16.584 ;
     RECT  4.601 22.752 4.732 24.552 ;
     RECT  3.953 10.464 4.837 11.448 ;
     RECT  4.637 3.024 4.849 3.144 ;
     RECT  4.273 43.872 4.849 43.896 ;
     RECT  4.597 25.68 4.853 33.336 ;
     RECT  4.421 14.208 4.876 14.52 ;
     RECT  4.732 22.992 4.885 24.552 ;
     RECT  4.403 36.96 4.885 39.24 ;
     RECT  4.849 43.872 4.885 44.472 ;
     RECT  4.837 10.464 4.924 12.168 ;
     RECT  4.885 36.96 4.925 39.768 ;
     RECT  4.853 25.68 4.961 32.904 ;
     RECT  3.953 7.632 4.993 9.144 ;
     RECT  4.924 10.464 4.993 11.448 ;
     RECT  4.849 3.024 5.065 3.192 ;
     RECT  4.876 14.496 5.065 14.52 ;
     RECT  2.704 41.28 5.125 41.4 ;
     RECT  4.525 5.712 5.137 5.784 ;
     RECT  4.169 20.256 5.137 20.28 ;
     RECT  4.921 21.264 5.137 21.288 ;
     RECT  4.885 43.152 5.171 44.472 ;
     RECT  4.705 19.008 5.173 19.272 ;
     RECT  5.137 5.712 5.177 5.832 ;
     RECT  5.125 41.28 5.209 42.12 ;
     RECT  4.961 27.744 5.213 32.904 ;
     RECT  5.209 41.28 5.213 42.744 ;
     RECT  5.177 5.76 5.245 5.832 ;
     RECT  5.245 5.76 5.285 6.264 ;
     RECT  4.885 22.992 5.389 24.696 ;
     RECT  4.961 25.68 5.389 26.76 ;
     RECT  5.171 43.824 5.389 44.472 ;
     RECT  5.065 3.024 5.465 3.384 ;
     RECT  5.173 18.48 5.537 19.272 ;
     RECT  5.213 27.744 5.573 30.216 ;
     RECT  5.213 41.904 5.645 42.744 ;
     RECT  5.389 22.992 5.681 26.76 ;
     RECT  5.425 12.768 5.701 12.792 ;
     RECT  4.453 34.464 5.857 35.448 ;
     RECT  5.645 41.904 5.861 41.928 ;
     RECT  5.065 14.496 5.965 14.856 ;
     RECT  4.925 36.96 6.037 38.76 ;
     RECT  4.925 39.744 6.037 39.768 ;
     RECT  4.993 7.632 6.073 11.448 ;
     RECT  5.537 18.768 6.181 19.272 ;
     RECT  5.137 20.256 6.181 21.288 ;
     RECT  5.573 27.744 6.257 28.488 ;
     RECT  5.573 30.144 6.289 30.216 ;
     RECT  5.213 31.344 6.289 32.904 ;
     RECT  5.701 12.768 6.325 13.512 ;
     RECT  5.965 14.496 6.325 15.192 ;
     RECT  6.073 40.896 6.361 40.92 ;
     RECT  5.857 34.464 6.397 35.928 ;
     RECT  6.037 36.96 6.397 39.768 ;
     RECT  6.325 12.768 6.421 15.192 ;
     RECT  5.465 3.072 6.433 3.384 ;
     RECT  5.681 23.136 6.433 26.76 ;
     RECT  6.257 27.744 6.433 27.816 ;
     RECT  6.421 12.48 6.437 15.192 ;
     RECT  5.389 43.824 6.437 45 ;
     RECT  6.433 3.024 6.469 3.384 ;
     RECT  5.749 4.56 6.469 4.584 ;
     RECT  6.437 44.448 6.473 45 ;
     RECT  6.437 12.48 6.508 12.504 ;
     RECT  6.469 3.024 6.509 4.584 ;
     RECT  6.509 3.024 6.577 4.008 ;
     RECT  6.397 34.464 6.613 39.768 ;
     RECT  6.613 34.128 6.653 39.768 ;
     RECT  6.437 13.872 6.689 15.192 ;
     RECT  6.289 30.144 6.725 33.096 ;
     RECT  5.285 5.808 6.757 6.264 ;
     RECT  6.073 7.392 6.757 11.448 ;
     RECT  6.653 37.632 6.829 39.768 ;
     RECT  6.361 40.896 6.829 41.736 ;
     RECT  6.181 18.768 6.853 21.288 ;
     RECT  6.577 2.832 6.865 4.008 ;
     RECT  6.725 30.144 6.973 30.312 ;
     RECT  6.829 37.632 6.973 41.736 ;
     RECT  6.757 5.808 7.081 11.448 ;
     RECT  4.706 16.56 7.117 16.584 ;
     RECT  6.725 31.392 7.153 33.096 ;
     RECT  6.653 34.128 7.153 36.552 ;
     RECT  6.433 23.136 7.189 27.816 ;
     RECT  7.081 5.808 7.381 11.784 ;
     RECT  6.853 18.768 7.477 21.384 ;
     RECT  7.189 22.56 7.477 27.816 ;
     RECT  7.477 18.768 7.573 27.816 ;
     RECT  7.381 5.04 7.585 11.784 ;
     RECT  6.689 14.112 7.585 15.192 ;
     RECT  7.117 16.56 7.585 16.68 ;
     RECT  6.973 37.632 7.585 42.312 ;
     RECT  7.573 18.768 7.621 28.008 ;
     RECT  7.585 37.632 7.669 42.792 ;
     RECT  6.865 2.784 7.808 4.008 ;
     RECT  7.585 4.992 7.808 11.784 ;
     RECT  7.585 14.112 7.808 16.68 ;
     RECT  7.621 18.768 7.808 28.44 ;
     RECT  6.973 29.856 7.808 30.312 ;
     RECT  7.153 31.392 7.808 36.552 ;
     RECT  7.669 37.584 7.808 42.792 ;
     RECT  6.473 44.976 7.808 45 ;
     RECT  7.808 2.148 7.912 45.372 ;
     RECT  7.912 2.418 8.104 45.102 ;
     RECT  8.104 4.848 8.165 28.824 ;
     RECT  8.165 4.848 8.633 11.256 ;
     RECT  8.104 31.392 8.669 39.288 ;
     RECT  8.633 4.992 8.849 11.256 ;
     RECT  8.669 31.392 8.849 33.096 ;
     RECT  8.165 12.336 9.029 28.824 ;
     RECT  8.104 29.856 9.097 30.168 ;
     RECT  8.849 31.392 9.097 33 ;
     RECT  8.669 34.176 9.205 39.288 ;
     RECT  9.205 34.176 9.216 39.336 ;
     RECT  8.849 5.04 9.277 11.256 ;
     RECT  9.029 12.336 9.277 16.68 ;
     RECT  9.277 5.04 9.281 16.68 ;
     RECT  9.281 9.264 9.425 16.68 ;
     RECT  9.216 38.208 9.565 39.336 ;
     RECT  9.313 40.8 9.565 40.824 ;
     RECT  9.097 29.856 9.677 33 ;
     RECT  9.029 17.904 9.709 28.824 ;
     RECT  9.677 29.856 9.709 32.952 ;
     RECT  9.565 38.208 9.709 40.824 ;
     RECT  8.104 41.904 9.709 43.56 ;
     RECT  9.425 9.264 9.713 9.288 ;
     RECT  9.216 34.176 9.713 37.08 ;
     RECT  9.713 34.176 9.817 35.736 ;
     RECT  8.104 2.832 9.889 3.432 ;
     RECT  9.889 2.832 9.925 3.72 ;
     RECT  9.425 10.416 9.929 16.68 ;
     RECT  9.709 38.208 9.965 43.56 ;
     RECT  9.929 15.552 10.105 16.68 ;
     RECT  9.965 43.2 10.177 43.56 ;
     RECT  9.097 45.168 10.217 45.192 ;
     RECT  9.709 17.904 10.225 32.952 ;
     RECT  10.105 15.552 10.285 16.92 ;
     RECT  10.225 17.904 10.285 28.392 ;
     RECT  9.281 5.04 10.289 8.232 ;
     RECT  9.965 38.208 10.289 42.024 ;
     RECT  9.929 10.416 10.325 14.472 ;
     RECT  10.225 29.664 10.325 32.952 ;
     RECT  9.925 2.832 10.433 3.912 ;
     RECT  10.289 5.28 10.537 8.232 ;
     RECT  10.285 15.552 10.541 28.392 ;
     RECT  9.817 33.984 10.757 35.736 ;
     RECT  10.541 15.552 10.829 28.152 ;
     RECT  10.829 15.552 10.865 17.736 ;
     RECT  9.713 36.72 10.897 37.08 ;
     RECT  10.537 5.28 11.113 8.952 ;
     RECT  10.289 40.032 11.113 42.024 ;
     RECT  10.177 43.2 11.113 43.896 ;
     RECT  10.433 2.832 11.149 3.864 ;
     RECT  10.325 12.48 11.221 14.472 ;
     RECT  10.325 10.416 11.261 11.4 ;
     RECT  11.113 5.28 11.365 9 ;
     RECT  11.261 10.416 11.365 11.256 ;
     RECT  10.289 38.208 11.365 39.048 ;
     RECT  11.113 40.032 11.365 43.896 ;
     RECT  10.325 32.832 11.401 32.952 ;
     RECT  10.757 33.984 11.401 34.008 ;
     RECT  11.221 12.48 11.459 14.904 ;
     RECT  11.365 38.208 11.459 43.896 ;
     RECT  10.829 19.056 11.509 28.152 ;
     RECT  10.325 29.664 11.509 31.8 ;
     RECT  11.459 41.04 11.549 43.896 ;
     RECT  11.549 42 11.593 43.896 ;
     RECT  11.149 2.304 11.729 3.864 ;
     RECT  10.897 36.48 11.761 37.08 ;
     RECT  11.459 38.208 11.761 40.056 ;
     RECT  11.761 36.48 11.765 40.056 ;
     RECT  11.593 43.824 11.833 43.896 ;
     RECT  11.459 12.48 11.873 14.712 ;
     RECT  11.365 5.28 11.977 11.256 ;
     RECT  11.401 32.832 11.977 34.008 ;
     RECT  10.757 34.992 11.977 35.304 ;
     RECT  11.977 32.832 11.989 35.304 ;
     RECT  11.765 36.48 11.989 36.504 ;
     RECT  11.729 2.304 12.017 3.336 ;
     RECT  10.865 16.272 12.049 17.736 ;
     RECT  11.509 19.056 12.049 31.8 ;
     RECT  11.873 13.104 12.125 14.712 ;
     RECT  11.833 43.824 12.157 44.472 ;
     RECT  12.125 13.104 12.197 13.128 ;
     RECT  12.157 43.824 12.301 44.664 ;
     RECT  11.977 5.232 12.409 11.256 ;
     RECT  12.409 4.56 12.661 11.256 ;
     RECT  12.661 4.56 12.764 11.448 ;
     RECT  12.049 16.272 12.769 31.8 ;
     RECT  11.989 32.832 12.769 36.504 ;
     RECT  12.764 4.368 12.805 11.448 ;
     RECT  12.769 16.272 12.913 36.504 ;
     RECT  12.017 2.736 13.208 3.336 ;
     RECT  12.805 4.368 13.208 11.496 ;
     RECT  12.125 14.352 13.208 14.712 ;
     RECT  12.913 16.272 13.208 36.552 ;
     RECT  11.765 37.68 13.208 40.056 ;
     RECT  11.593 42 13.208 42.744 ;
     RECT  12.301 43.824 13.208 45 ;
     RECT  13.208 2.148 13.312 45.372 ;
     RECT  13.312 2.256 13.504 45.102 ;
     RECT  13.504 10.656 13.745 33.912 ;
     RECT  13.504 41.952 13.889 42.024 ;
     RECT  13.504 4.656 13.925 9.096 ;
     RECT  13.925 5.088 14.141 9.096 ;
     RECT  13.745 15.456 14.213 33.912 ;
     RECT  14.141 6.288 14.321 9.096 ;
     RECT  14.321 6.576 14.393 9.096 ;
     RECT  13.504 34.992 14.393 39.24 ;
     RECT  14.393 34.992 14.609 37.032 ;
     RECT  14.605 40.416 14.677 40.44 ;
     RECT  14.213 18.144 14.681 33.912 ;
     RECT  14.393 6.672 14.713 9.096 ;
     RECT  14.681 18.768 14.713 33.912 ;
     RECT  14.609 34.992 14.713 36.36 ;
     RECT  14.393 38.016 14.753 39.24 ;
     RECT  14.677 40.416 14.785 40.488 ;
     RECT  14.753 38.688 14.819 39.24 ;
     RECT  13.745 10.656 14.821 14.472 ;
     RECT  14.213 15.456 14.821 15.48 ;
     RECT  14.819 38.688 14.86 39 ;
     RECT  14.821 10.656 14.861 15.48 ;
     RECT  14.713 18.768 14.861 36.36 ;
     RECT  14.213 16.512 14.867 17.112 ;
     RECT  14.861 10.656 14.893 11.448 ;
     RECT  14.713 6.672 14.965 9.192 ;
     RECT  14.893 10.512 14.965 11.448 ;
     RECT  13.889 41.952 15.041 41.976 ;
     RECT  14.861 12.768 15.181 15.48 ;
     RECT  14.867 16.512 15.181 17.064 ;
     RECT  14.785 40.416 15.181 40.824 ;
     RECT  14.965 6.672 15.185 11.448 ;
     RECT  14.141 5.088 15.253 5.304 ;
     RECT  15.217 43.632 15.349 43.656 ;
     RECT  14.785 45.024 15.349 45.048 ;
     RECT  15.349 43.632 15.395 45.048 ;
     RECT  13.504 2.256 15.397 3.144 ;
     RECT  15.253 4.56 15.397 5.304 ;
     RECT  15.395 43.632 15.397 44.472 ;
     RECT  14.861 32.832 15.649 36.36 ;
     RECT  15.397 2.256 15.757 5.304 ;
     RECT  15.397 43.392 15.757 44.472 ;
     RECT  15.181 40.416 15.833 40.968 ;
     RECT  14.861 19.056 15.865 21 ;
     RECT  15.757 2.256 15.869 5.64 ;
     RECT  15.869 2.736 15.875 5.64 ;
     RECT  15.875 2.736 15.913 3.096 ;
     RECT  15.181 12.768 15.973 17.064 ;
     RECT  15.875 4.56 16.019 5.64 ;
     RECT  15.833 40.464 16.045 40.968 ;
     RECT  15.913 3.072 16.049 3.096 ;
     RECT  16.045 40.464 16.049 41.928 ;
     RECT  15.973 12.72 16.081 17.064 ;
     RECT  15.865 18.432 16.081 21 ;
     RECT  16.049 40.8 16.081 41.928 ;
     RECT  14.86 38.688 16.153 38.712 ;
     RECT  15.185 6.672 16.189 11.064 ;
     RECT  16.081 12.72 16.189 21 ;
     RECT  15.757 43.296 16.265 44.472 ;
     RECT  16.189 6.672 16.297 21 ;
     RECT  14.861 22.128 16.405 31.8 ;
     RECT  15.649 32.832 16.405 36.504 ;
     RECT  16.081 40.8 16.445 42.168 ;
     RECT  16.297 6.672 16.595 21.048 ;
     RECT  16.405 22.128 16.625 36.504 ;
     RECT  16.595 6.672 16.661 14.856 ;
     RECT  15.404 37.584 16.693 37.608 ;
     RECT  16.153 38.688 16.693 39.24 ;
     RECT  16.019 4.8 16.801 5.64 ;
     RECT  16.661 6.672 16.801 6.888 ;
     RECT  16.265 43.296 16.949 43.416 ;
     RECT  16.801 4.8 16.979 6.888 ;
     RECT  16.595 16.464 16.981 21.048 ;
     RECT  16.625 28.944 16.981 36.504 ;
     RECT  16.693 37.584 16.981 39.24 ;
     RECT  16.445 41.904 17.053 42.168 ;
     RECT  16.981 28.944 17.057 39.24 ;
     RECT  16.981 16.464 17.089 21.144 ;
     RECT  16.625 22.128 17.089 27.48 ;
     RECT  17.057 39.216 17.089 39.24 ;
     RECT  17.057 28.944 17.165 38.232 ;
     RECT  17.089 16.464 17.201 27.48 ;
     RECT  16.445 40.8 17.309 40.824 ;
     RECT  16.979 6.432 17.345 6.888 ;
     RECT  17.053 2.88 17.377 2.904 ;
     RECT  17.165 28.944 17.381 36.792 ;
     RECT  17.377 2.256 17.417 2.904 ;
     RECT  17.201 18.432 17.453 27.48 ;
     RECT  17.453 21.792 17.701 27.48 ;
     RECT  17.701 21.792 17.773 27.72 ;
     RECT  16.979 4.8 17.845 5.304 ;
     RECT  17.053 41.904 17.953 43.128 ;
     RECT  17.089 39.216 17.989 39.768 ;
     RECT  17.345 6.432 18.061 6.792 ;
     RECT  17.381 29.04 18.169 36.792 ;
     RECT  17.165 37.824 18.169 38.232 ;
     RECT  17.953 41.472 18.181 43.128 ;
     RECT  16.265 44.448 18.181 44.472 ;
     RECT  17.845 4.56 18.277 5.304 ;
     RECT  17.201 16.464 18.277 16.968 ;
     RECT  18.061 6.384 18.457 6.792 ;
     RECT  17.417 2.256 18.608 2.28 ;
     RECT  18.277 4.416 18.608 5.304 ;
     RECT  18.457 6.336 18.608 6.792 ;
     RECT  16.661 7.92 18.608 14.856 ;
     RECT  18.277 16.032 18.608 16.968 ;
     RECT  17.453 18.432 18.608 20.712 ;
     RECT  17.773 21.792 18.608 27.768 ;
     RECT  18.169 29.04 18.608 38.232 ;
     RECT  17.989 39.216 18.608 40.2 ;
     RECT  18.181 41.472 18.608 44.472 ;
     RECT  18.608 2.148 18.712 45.372 ;
     RECT  18.712 2.418 18.904 45.102 ;
     RECT  18.904 16.032 18.929 20.952 ;
     RECT  18.904 9.36 18.965 14.952 ;
     RECT  18.904 42 19.073 43.08 ;
     RECT  18.904 28.8 19.145 35.256 ;
     RECT  18.904 3.936 19.187 8.28 ;
     RECT  18.904 36.24 19.217 40.584 ;
     RECT  18.904 22.176 19.289 27.624 ;
     RECT  19.187 6.384 19.433 8.28 ;
     RECT  19.187 4.224 19.613 5.304 ;
     RECT  19.433 7.872 19.649 8.28 ;
     RECT  19.217 36.24 19.685 39.432 ;
     RECT  18.904 45.024 19.897 45.048 ;
     RECT  19.073 42.672 19.957 43.08 ;
     RECT  19.897 44.592 19.957 45.048 ;
     RECT  19.217 40.56 19.973 40.584 ;
     RECT  19.145 34.992 20.113 35.256 ;
     RECT  19.685 36.24 20.113 36.264 ;
     RECT  19.145 28.8 20.189 33.624 ;
     RECT  19.957 42.672 20.195 45.048 ;
     RECT  18.904 2.496 20.221 2.856 ;
     RECT  19.433 6.384 20.401 6.696 ;
     RECT  19.649 7.872 20.401 7.944 ;
     RECT  19.613 4.416 20.437 5.304 ;
     RECT  20.401 6.384 20.437 7.944 ;
     RECT  18.965 9.36 20.473 14.712 ;
     RECT  20.437 4.416 20.477 7.944 ;
     RECT  20.189 28.8 20.477 30.168 ;
     RECT  20.473 9.36 20.543 14.856 ;
     RECT  18.929 16.416 20.545 20.952 ;
     RECT  20.195 42.72 20.585 45.048 ;
     RECT  19.289 22.176 20.653 23.304 ;
     RECT  19.289 24.336 20.653 27.624 ;
     RECT  20.653 22.176 20.797 27.624 ;
     RECT  20.477 28.8 20.797 30.12 ;
     RECT  20.189 31.2 20.797 33.624 ;
     RECT  20.113 34.992 20.797 36.264 ;
     RECT  20.477 5.568 20.801 7.944 ;
     RECT  20.543 9.36 20.833 15.192 ;
     RECT  20.545 16.416 20.833 21 ;
     RECT  19.685 37.68 20.869 39.432 ;
     RECT  20.477 4.416 20.873 4.44 ;
     RECT  20.221 2.496 20.909 3.432 ;
     RECT  20.585 42.72 21.053 43.944 ;
     RECT  20.833 9.36 21.121 21 ;
     RECT  20.869 37.68 21.197 39.624 ;
     RECT  20.801 5.568 21.203 7.56 ;
     RECT  20.797 22.176 21.481 30.12 ;
     RECT  20.797 31.2 21.481 36.264 ;
     RECT  21.197 39.6 21.481 39.624 ;
     RECT  21.197 37.68 21.517 38.232 ;
     RECT  20.909 2.784 21.589 3.432 ;
     RECT  21.121 9.312 21.661 21 ;
     RECT  21.481 22.176 21.661 36.264 ;
     RECT  20.585 45.024 21.701 45.048 ;
     RECT  21.517 37.44 21.737 38.232 ;
     RECT  21.589 2.784 21.913 3.624 ;
     RECT  21.661 9.312 22.057 36.264 ;
     RECT  21.203 5.856 22.069 7.56 ;
     RECT  22.069 5.856 22.165 7.944 ;
     RECT  22.057 9.312 22.165 36.312 ;
     RECT  22.165 5.856 22.169 36.312 ;
     RECT  21.913 2.736 22.417 3.624 ;
     RECT  22.169 31.248 22.417 36.312 ;
     RECT  21.737 37.44 22.417 38.184 ;
     RECT  22.169 5.856 22.421 30.12 ;
     RECT  22.421 5.856 22.489 27.048 ;
     RECT  21.053 43.92 22.633 43.944 ;
     RECT  22.417 2.256 22.705 3.624 ;
     RECT  21.805 4.608 22.705 4.632 ;
     RECT  22.705 2.256 22.741 4.632 ;
     RECT  22.489 5.76 22.741 27.048 ;
     RECT  22.741 2.256 22.789 27.048 ;
     RECT  22.417 31.248 22.885 38.184 ;
     RECT  22.633 43.92 22.885 44.376 ;
     RECT  22.885 31.248 22.981 38.52 ;
     RECT  21.481 39.6 22.981 39.864 ;
     RECT  22.981 31.248 23.173 40.008 ;
     RECT  22.789 4.656 23.389 27.048 ;
     RECT  22.421 28.032 23.389 30.12 ;
     RECT  22.813 41.664 23.389 41.688 ;
     RECT  21.053 42.72 23.641 42.744 ;
     RECT  22.885 43.92 23.641 45.048 ;
     RECT  23.389 4.656 23.677 30.12 ;
     RECT  23.173 31.248 23.677 40.152 ;
     RECT  22.789 2.256 23.893 3.624 ;
     RECT  23.893 2.256 24.008 3.672 ;
     RECT  23.677 4.656 24.008 40.152 ;
     RECT  23.389 41.664 24.008 41.736 ;
     RECT  23.641 42.72 24.008 45.048 ;
     RECT  24.008 2.148 24.112 45.372 ;
     RECT  24.112 2.418 24.304 45.102 ;
     RECT  24.304 38.976 24.401 40.488 ;
     RECT  24.304 2.832 24.419 14.712 ;
     RECT  24.304 18.768 24.437 36.264 ;
     RECT  24.419 2.832 24.473 6.936 ;
     RECT  24.473 2.832 24.515 6.888 ;
     RECT  24.437 18.768 24.573 28.008 ;
     RECT  24.515 2.832 24.725 3.384 ;
     RECT  24.304 41.664 24.761 44.712 ;
     RECT  24.812 0.096 24.899 0.12 ;
     RECT  24.761 42.528 25.043 44.712 ;
     RECT  24.304 15.984 25.085 17.736 ;
     RECT  24.437 29.616 25.091 36.264 ;
     RECT  25.091 29.616 25.121 30.456 ;
     RECT  24.419 7.92 25.139 14.712 ;
     RECT  24.573 18.768 25.157 23.4 ;
     RECT  25.139 8.16 25.165 14.712 ;
     RECT  24.304 37.584 25.229 37.992 ;
     RECT  25.165 8.736 25.301 14.712 ;
     RECT  25.091 31.536 25.373 36.264 ;
     RECT  25.121 29.712 25.445 30.456 ;
     RECT  25.085 16.896 25.477 17.736 ;
     RECT  25.157 18.768 25.477 20.184 ;
     RECT  25.229 37.632 25.553 37.992 ;
     RECT  25.301 14.688 25.58 14.712 ;
     RECT  25.157 21.168 25.661 23.4 ;
     RECT  25.58 14.688 25.667 15.48 ;
     RECT  24.401 39.36 25.693 40.488 ;
     RECT  24.573 24.384 25.697 28.008 ;
     RECT  25.373 31.536 25.697 35.304 ;
     RECT  25.043 42.528 25.729 42.696 ;
     RECT  25.043 43.968 25.729 44.712 ;
     RECT  25.661 21.168 25.733 21.432 ;
     RECT  25.693 39.216 25.981 40.488 ;
     RECT  25.729 41.76 25.981 42.696 ;
     RECT  25.733 21.168 26.021 21.192 ;
     RECT  25.981 39.216 26.057 42.696 ;
     RECT  25.661 22.464 26.089 23.4 ;
     RECT  25.697 24.384 26.089 26.76 ;
     RECT  24.725 2.832 26.125 3.336 ;
     RECT  24.515 4.56 26.125 6.888 ;
     RECT  25.697 27.984 26.129 28.008 ;
     RECT  25.697 31.536 26.129 35.256 ;
     RECT  25.477 16.896 26.161 20.184 ;
     RECT  26.161 16.896 26.165 21.144 ;
     RECT  25.553 37.632 26.233 37.656 ;
     RECT  26.057 39.216 26.561 42.552 ;
     RECT  26.233 37.584 26.737 37.656 ;
     RECT  26.125 2.832 26.777 7.368 ;
     RECT  26.089 22.464 26.777 26.76 ;
     RECT  26.777 22.56 26.849 26.76 ;
     RECT  26.561 39.216 26.881 39.96 ;
     RECT  25.301 8.736 26.957 13.608 ;
     RECT  26.737 37.584 26.957 37.992 ;
     RECT  25.729 43.968 26.957 44.904 ;
     RECT  26.957 8.736 27.025 10.68 ;
     RECT  26.521 15.792 27.061 15.816 ;
     RECT  26.165 16.896 27.061 17.448 ;
     RECT  26.777 3.168 27.065 7.368 ;
     RECT  25.667 14.688 27.169 14.808 ;
     RECT  27.061 15.792 27.169 17.448 ;
     RECT  26.129 31.536 27.169 31.8 ;
     RECT  26.129 32.976 27.169 35.256 ;
     RECT  26.165 19.008 27.277 21.144 ;
     RECT  27.061 27.888 27.277 27.912 ;
     RECT  27.169 31.536 27.277 35.256 ;
     RECT  27.277 27.888 27.313 28.584 ;
     RECT  25.445 29.712 27.313 30.12 ;
     RECT  27.065 3.168 27.317 5.16 ;
     RECT  26.957 11.664 27.353 13.608 ;
     RECT  25.945 36.48 27.353 36.504 ;
     RECT  26.561 41.184 27.353 42.552 ;
     RECT  27.277 18.768 27.389 21.144 ;
     RECT  26.957 37.632 27.445 37.992 ;
     RECT  26.881 39.024 27.445 39.96 ;
     RECT  27.353 11.712 27.457 13.608 ;
     RECT  27.169 14.688 27.457 17.448 ;
     RECT  27.317 3.168 27.461 5.016 ;
     RECT  27.445 37.632 27.491 39.96 ;
     RECT  27.491 37.632 27.497 38.424 ;
     RECT  27.491 39.888 27.533 39.96 ;
     RECT  27.065 6.288 27.637 7.368 ;
     RECT  27.025 8.448 27.637 10.68 ;
     RECT  27.313 27.888 27.745 30.12 ;
     RECT  27.277 31.536 27.781 35.352 ;
     RECT  27.461 3.168 27.817 4.968 ;
     RECT  27.457 11.712 27.817 17.448 ;
     RECT  27.389 18.768 27.817 20.184 ;
     RECT  27.637 6.288 27.821 10.68 ;
     RECT  27.821 8.496 27.923 10.68 ;
     RECT  27.745 27.888 27.923 30.264 ;
     RECT  27.923 27.888 28.001 30.216 ;
     RECT  27.923 9.6 28.109 10.68 ;
     RECT  27.781 31.248 28.141 35.352 ;
     RECT  27.853 21.408 28.177 21.48 ;
     RECT  26.849 22.656 28.177 26.76 ;
     RECT  26.957 44.208 28.211 44.904 ;
     RECT  27.923 8.544 28.253 8.568 ;
     RECT  27.353 41.184 28.429 42.024 ;
     RECT  28.141 31.248 28.501 35.88 ;
     RECT  28.177 21.408 28.537 26.76 ;
     RECT  27.533 39.888 28.717 39.912 ;
     RECT  28.109 9.84 28.825 10.68 ;
     RECT  27.817 11.712 28.837 20.184 ;
     RECT  28.537 21.36 28.837 26.76 ;
     RECT  28.429 41.184 28.837 42.792 ;
     RECT  28.211 44.208 28.837 44.664 ;
     RECT  27.817 3.12 29.041 4.968 ;
     RECT  28.001 27.888 29.041 28.584 ;
     RECT  28.001 29.616 29.041 30.216 ;
     RECT  28.501 31.248 29.077 36.456 ;
     RECT  27.497 37.68 29.077 38.424 ;
     RECT  29.041 3.12 29.113 5.016 ;
     RECT  27.821 6.288 29.113 6.984 ;
     RECT  29.113 3.12 29.408 6.984 ;
     RECT  29.077 8.304 29.408 8.328 ;
     RECT  28.825 9.84 29.408 10.728 ;
     RECT  28.837 11.712 29.408 26.76 ;
     RECT  29.041 27.888 29.408 30.216 ;
     RECT  29.077 31.248 29.408 38.424 ;
     RECT  28.717 39.6 29.408 39.912 ;
     RECT  28.837 41.184 29.408 44.664 ;
     RECT  29.408 2.148 29.512 45.372 ;
     RECT  29.512 2.418 29.704 45.102 ;
     RECT  29.704 15.408 29.801 27.096 ;
     RECT  29.704 29.568 29.873 38.136 ;
     RECT  29.873 34.608 29.945 38.136 ;
     RECT  29.704 39.6 29.981 39.624 ;
     RECT  29.704 2.64 30.124 5.496 ;
     RECT  29.704 41.664 30.197 45.048 ;
     RECT  29.704 28.224 30.269 28.584 ;
     RECT  29.801 18.816 30.305 27.096 ;
     RECT  30.305 18.816 30.413 22.008 ;
     RECT  30.413 18.816 30.563 21.576 ;
     RECT  29.704 10.176 30.665 14.424 ;
     RECT  30.305 22.992 30.697 27.096 ;
     RECT  30.124 2.784 30.733 5.496 ;
     RECT  29.704 6.624 30.733 7.512 ;
     RECT  30.697 22.992 30.737 28.008 ;
     RECT  30.563 18.816 30.755 21.528 ;
     RECT  29.704 9.168 30.805 9.192 ;
     RECT  30.665 10.176 30.805 13.128 ;
     RECT  30.197 41.904 31.025 45.048 ;
     RECT  29.801 15.408 31.061 17.736 ;
     RECT  29.945 34.896 31.061 38.136 ;
     RECT  30.665 14.208 31.129 14.424 ;
     RECT  31.061 15.408 31.129 17.448 ;
     RECT  31.025 41.904 31.139 44.472 ;
     RECT  31.061 34.896 31.205 35.832 ;
     RECT  30.733 2.784 31.285 7.512 ;
     RECT  31.205 34.896 31.309 35.688 ;
     RECT  31.201 40.8 31.333 40.824 ;
     RECT  30.805 9.168 31.421 13.128 ;
     RECT  30.737 22.992 31.453 26.856 ;
     RECT  31.309 34.848 31.561 35.688 ;
     RECT  29.873 29.568 31.705 33.624 ;
     RECT  30.737 27.888 31.741 28.008 ;
     RECT  31.705 29.136 31.741 33.624 ;
     RECT  31.061 36.96 31.741 38.136 ;
     RECT  31.333 39.888 31.745 40.824 ;
     RECT  31.421 10.656 31.777 13.128 ;
     RECT  31.129 14.208 31.777 17.448 ;
     RECT  31.453 22.752 31.781 26.856 ;
     RECT  31.781 24.192 31.813 26.856 ;
     RECT  31.741 27.888 31.813 33.624 ;
     RECT  31.745 40.56 31.849 40.824 ;
     RECT  31.139 41.904 31.849 44.184 ;
     RECT  31.813 24.192 31.861 33.624 ;
     RECT  30.755 18.816 31.885 20.184 ;
     RECT  31.421 9.168 31.889 9.192 ;
     RECT  31.561 34.8 31.907 35.688 ;
     RECT  31.285 2.256 31.925 7.512 ;
     RECT  31.861 24.192 32.033 33.816 ;
     RECT  31.849 40.56 32.033 44.184 ;
     RECT  30.755 21.504 32.065 21.528 ;
     RECT  31.777 10.656 32.101 17.448 ;
     RECT  32.033 41.904 32.141 44.184 ;
     RECT  31.781 22.752 32.173 23.16 ;
     RECT  32.033 24.192 32.285 33.624 ;
     RECT  31.925 2.256 32.357 7.464 ;
     RECT  32.101 10.656 32.357 17.688 ;
     RECT  31.741 36.96 32.425 38.184 ;
     RECT  32.065 21.456 32.485 21.528 ;
     RECT  31.907 34.848 32.533 35.688 ;
     RECT  32.425 36.816 32.533 38.184 ;
     RECT  32.357 2.832 32.609 7.464 ;
     RECT  32.357 10.656 32.717 13.128 ;
     RECT  32.533 34.848 32.893 38.184 ;
     RECT  32.893 34.8 32.965 38.184 ;
     RECT  32.173 22.704 32.993 23.16 ;
     RECT  32.285 24.192 32.993 27.144 ;
     RECT  32.141 42.192 33.013 44.184 ;
     RECT  32.965 34.8 33.113 39.384 ;
     RECT  31.885 18.72 33.145 20.184 ;
     RECT  32.485 21.312 33.145 21.528 ;
     RECT  32.033 40.56 33.181 40.824 ;
     RECT  32.285 28.128 33.205 33.624 ;
     RECT  33.113 34.8 33.205 37.608 ;
     RECT  32.609 3.888 33.217 7.464 ;
     RECT  32.929 8.64 33.217 8.664 ;
     RECT  33.145 18.72 33.217 21.528 ;
     RECT  32.717 10.656 33.253 11.976 ;
     RECT  32.357 14.208 33.289 17.688 ;
     RECT  33.217 18.72 33.289 21.672 ;
     RECT  33.253 10.368 33.401 11.976 ;
     RECT  32.609 2.832 33.433 2.856 ;
     RECT  33.401 10.56 33.437 11.976 ;
     RECT  33.217 3.888 33.58 8.664 ;
     RECT  32.717 12.96 33.58 13.128 ;
     RECT  33.289 14.208 33.599 21.672 ;
     RECT  32.993 22.704 33.599 27.144 ;
     RECT  33.58 13.104 33.613 13.128 ;
     RECT  33.599 14.208 33.637 27.144 ;
     RECT  33.205 28.128 33.637 37.608 ;
     RECT  33.013 42.192 33.649 44.376 ;
     RECT  33.437 10.56 33.683 11.88 ;
     RECT  33.721 8.928 33.973 8.952 ;
     RECT  33.113 39.36 34.028 39.384 ;
     RECT  33.181 40.56 34.028 41.208 ;
     RECT  34.028 39.36 34.153 41.208 ;
     RECT  33.649 42.192 34.153 44.76 ;
     RECT  34.153 39.36 34.165 44.76 ;
     RECT  33.613 13.104 34.189 13.224 ;
     RECT  33.637 14.208 34.189 37.608 ;
     RECT  33.683 10.56 34.621 11.256 ;
     RECT  33.58 3.888 34.765 7.704 ;
     RECT  34.621 10.416 34.801 11.256 ;
     RECT  33.433 2.256 34.808 2.856 ;
     RECT  34.765 3.888 34.808 7.848 ;
     RECT  33.973 8.928 34.808 9.096 ;
     RECT  34.801 10.416 34.808 11.976 ;
     RECT  34.189 13.104 34.808 37.608 ;
     RECT  34.165 38.688 34.808 44.76 ;
     RECT  34.808 2.148 34.912 45.372 ;
     RECT  34.912 2.256 35.104 45.102 ;
     RECT  35.104 40.32 35.165 42.264 ;
     RECT  35.104 2.256 35.219 10.824 ;
     RECT  35.104 38.16 35.309 38.712 ;
     RECT  35.165 40.32 35.309 42.216 ;
     RECT  35.104 11.952 35.363 32.328 ;
     RECT  35.363 12.432 35.404 32.328 ;
     RECT  35.404 21.504 35.489 32.328 ;
     RECT  35.404 12.432 35.525 20.328 ;
     RECT  35.489 21.504 35.525 24.552 ;
     RECT  35.309 40.32 35.741 41.496 ;
     RECT  35.219 2.784 35.777 10.824 ;
     RECT  35.104 33.6 35.921 36.936 ;
     RECT  35.104 43.824 36.137 45 ;
     RECT  35.741 40.32 36.209 41.064 ;
     RECT  35.777 4.944 36.349 10.824 ;
     RECT  35.525 12.432 36.529 13.128 ;
     RECT  35.525 14.688 36.529 20.328 ;
     RECT  35.525 21.504 36.529 23.16 ;
     RECT  35.921 36.432 36.529 36.936 ;
     RECT  35.309 38.16 36.529 38.184 ;
     RECT  35.489 25.536 36.569 32.328 ;
     RECT  35.525 24.192 36.601 24.552 ;
     RECT  36.569 25.536 36.601 25.56 ;
     RECT  36.349 4.944 36.605 11.064 ;
     RECT  36.569 26.592 36.637 32.328 ;
     RECT  35.921 33.6 36.637 35.256 ;
     RECT  36.529 12.432 36.709 13.656 ;
     RECT  36.529 14.688 36.709 23.16 ;
     RECT  36.601 24.192 36.709 25.56 ;
     RECT  36.637 26.592 36.713 35.256 ;
     RECT  36.137 44.112 36.785 45 ;
     RECT  36.709 12.432 36.893 23.16 ;
     RECT  36.493 40.128 36.925 40.152 ;
     RECT  36.893 12.432 36.961 21.528 ;
     RECT  36.529 36.432 36.961 38.184 ;
     RECT  36.713 28.272 36.965 35.256 ;
     RECT  36.605 4.944 36.997 6.888 ;
     RECT  36.997 4.512 37.001 6.888 ;
     RECT  37.001 5.76 37.043 6.888 ;
     RECT  36.961 36.288 37.069 38.184 ;
     RECT  36.965 28.992 37.1 35.256 ;
     RECT  37.069 36.288 37.1 38.472 ;
     RECT  37.1 28.992 37.105 38.472 ;
     RECT  36.785 44.112 37.141 44.76 ;
     RECT  37.043 6.048 37.145 6.888 ;
     RECT  37.105 28.992 37.145 38.808 ;
     RECT  37.141 41.808 37.177 41.832 ;
     RECT  37.141 43.152 37.177 44.76 ;
     RECT  37.145 30.096 37.217 38.808 ;
     RECT  37.177 41.808 37.235 44.76 ;
     RECT  36.605 7.872 37.249 11.064 ;
     RECT  36.961 12.096 37.249 21.528 ;
     RECT  35.777 2.784 37.321 3.384 ;
     RECT  36.925 39.84 37.465 40.152 ;
     RECT  37.465 39.312 37.469 40.152 ;
     RECT  36.709 24.144 37.573 25.56 ;
     RECT  36.713 26.592 37.573 27.288 ;
     RECT  37.249 7.872 37.649 21.528 ;
     RECT  37.235 42.144 37.649 44.76 ;
     RECT  37.217 30.096 37.667 38.184 ;
     RECT  37.145 6.192 37.681 6.888 ;
     RECT  37.649 7.872 37.681 21.24 ;
     RECT  37.573 24.144 37.681 27.288 ;
     RECT  37.321 2.304 37.825 3.384 ;
     RECT  37.681 6.192 37.937 21.24 ;
     RECT  36.893 22.8 38.077 23.16 ;
     RECT  37.681 24.144 38.077 27.384 ;
     RECT  38.077 22.8 38.113 27.384 ;
     RECT  37.001 4.512 38.149 4.536 ;
     RECT  37.937 6.192 38.189 14.424 ;
     RECT  38.113 22.8 38.195 27.96 ;
     RECT  38.189 6.192 38.257 9.096 ;
     RECT  37.937 15.408 38.261 21.24 ;
     RECT  38.257 5.952 38.293 9.096 ;
     RECT  38.195 24.336 38.329 27.96 ;
     RECT  37.145 28.992 38.329 29.064 ;
     RECT  37.469 39.312 38.657 39.864 ;
     RECT  37.825 2.304 38.773 3.432 ;
     RECT  38.149 4.464 38.773 4.536 ;
     RECT  38.657 39.648 38.797 39.864 ;
     RECT  37.667 30.096 38.801 32.568 ;
     RECT  38.797 39.648 38.869 40.44 ;
     RECT  38.189 10.656 38.941 14.424 ;
     RECT  38.941 10.656 39.089 14.616 ;
     RECT  38.261 15.696 39.157 21.24 ;
     RECT  38.195 22.8 39.157 23.16 ;
     RECT  38.329 24.336 39.193 29.064 ;
     RECT  38.801 30.096 39.193 30.12 ;
     RECT  39.157 15.696 39.301 23.16 ;
     RECT  37.649 42.144 39.301 44.184 ;
     RECT  38.761 45.168 39.301 45.192 ;
     RECT  39.301 15.696 39.445 23.304 ;
     RECT  39.193 24.336 39.445 30.12 ;
     RECT  39.301 42.144 39.661 45.192 ;
     RECT  38.293 5.856 39.733 9.096 ;
     RECT  39.089 12.24 39.733 14.616 ;
     RECT  39.445 15.696 39.733 30.12 ;
     RECT  39.733 12.24 39.805 30.12 ;
     RECT  38.801 31.104 39.805 32.568 ;
     RECT  38.773 2.304 39.913 4.536 ;
     RECT  39.733 5.808 39.913 9.096 ;
     RECT  37.667 33.552 39.913 38.184 ;
     RECT  38.869 39.648 39.913 40.872 ;
     RECT  39.913 33.552 39.985 40.872 ;
     RECT  39.661 41.904 39.985 45.192 ;
     RECT  39.805 12.24 40.093 32.568 ;
     RECT  39.985 33.552 40.093 45.192 ;
     RECT  39.913 2.304 40.208 9.096 ;
     RECT  39.089 10.656 40.208 11.256 ;
     RECT  40.093 12.24 40.208 45.192 ;
     RECT  40.208 2.148 40.312 45.372 ;
     RECT  40.312 2.418 40.504 45.192 ;
     RECT  40.504 41.664 40.709 45.192 ;
     RECT  40.504 11.952 40.781 37.608 ;
     RECT  40.504 5.856 40.817 10.68 ;
     RECT  40.817 5.856 40.853 7.992 ;
     RECT  40.709 43.296 40.853 45.192 ;
     RECT  40.504 3.072 40.889 4.68 ;
     RECT  40.781 21.696 40.961 37.608 ;
     RECT  40.504 39.84 41.027 40.44 ;
     RECT  40.961 29.568 41.069 37.608 ;
     RECT  40.853 44.112 41.069 44.424 ;
     RECT  40.889 3.072 41.525 4.488 ;
     RECT  40.781 11.952 41.569 20.184 ;
     RECT  40.961 21.696 41.573 28.104 ;
     RECT  41.573 22.752 41.603 28.104 ;
     RECT  40.853 6.288 41.681 7.992 ;
     RECT  41.069 29.616 41.681 37.608 ;
     RECT  40.709 41.664 41.681 42.264 ;
     RECT  41.027 40.416 41.713 40.44 ;
     RECT  40.817 8.976 41.753 10.68 ;
     RECT  41.525 2.784 41.821 4.488 ;
     RECT  41.821 2.736 41.893 4.488 ;
     RECT  41.681 6.288 41.893 7.32 ;
     RECT  41.681 41.904 41.893 42.264 ;
     RECT  41.893 41.904 41.929 42.36 ;
     RECT  41.713 40.416 42.005 40.872 ;
     RECT  41.569 11.76 42.227 20.184 ;
     RECT  41.069 44.352 42.229 44.424 ;
     RECT  42.227 15.984 42.253 20.184 ;
     RECT  41.573 21.696 42.253 21.72 ;
     RECT  41.893 2.736 42.257 7.32 ;
     RECT  42.227 14.4 42.257 14.808 ;
     RECT  42.257 2.88 42.293 7.32 ;
     RECT  42.253 15.984 42.293 21.72 ;
     RECT  41.681 35.136 42.293 37.608 ;
     RECT  41.603 23.136 42.433 28.104 ;
     RECT  41.681 29.616 42.433 33.96 ;
     RECT  42.229 44.064 42.433 44.424 ;
     RECT  41.929 41.904 42.469 43.032 ;
     RECT  42.433 44.064 42.469 45 ;
     RECT  42.001 38.688 42.497 38.712 ;
     RECT  42.005 40.608 42.509 40.872 ;
     RECT  42.497 38.688 42.581 39.384 ;
     RECT  42.293 2.88 42.617 5.016 ;
     RECT  42.293 35.232 42.797 37.608 ;
     RECT  41.753 8.976 42.865 9 ;
     RECT  42.293 16.608 42.901 21.72 ;
     RECT  42.433 23.136 42.901 33.96 ;
     RECT  42.865 8.976 42.973 9.288 ;
     RECT  42.901 16.608 42.977 33.96 ;
     RECT  42.509 40.848 43.013 40.872 ;
     RECT  42.797 35.232 43.193 37.464 ;
     RECT  42.257 14.496 43.333 14.808 ;
     RECT  42.293 6.288 43.361 7.32 ;
     RECT  43.361 5.712 43.445 7.32 ;
     RECT  43.333 14.496 43.477 15.192 ;
     RECT  42.469 41.904 43.517 45 ;
     RECT  43.477 14.496 43.532 15.288 ;
     RECT  42.977 16.608 43.532 30.12 ;
     RECT  43.445 6.528 43.549 7.32 ;
     RECT  42.617 2.88 43.697 4.584 ;
     RECT  42.581 38.688 43.729 38.712 ;
     RECT  43.532 14.496 43.765 30.12 ;
     RECT  42.973 8.976 43.769 9.336 ;
     RECT  43.729 38.688 43.841 38.76 ;
     RECT  43.697 2.88 43.909 3.672 ;
     RECT  43.765 14.4 43.913 30.12 ;
     RECT  43.769 9.264 43.949 9.336 ;
     RECT  43.517 41.904 43.949 44.952 ;
     RECT  43.913 18.144 44.005 30.12 ;
     RECT  42.977 31.776 44.005 33.96 ;
     RECT  43.913 14.4 44.021 16.968 ;
     RECT  43.193 36.576 44.108 37.464 ;
     RECT  44.021 16.944 44.165 16.968 ;
     RECT  44.108 36.576 44.195 37.848 ;
     RECT  43.949 41.904 44.195 42.84 ;
     RECT  41.753 10.656 44.305 10.68 ;
     RECT  42.227 11.76 44.305 13.32 ;
     RECT  43.949 9.264 44.309 9.288 ;
     RECT  44.005 18.144 44.345 33.96 ;
     RECT  43.193 35.232 44.377 35.4 ;
     RECT  44.195 36.576 44.377 37.416 ;
     RECT  44.377 35.232 44.389 37.416 ;
     RECT  44.149 40.128 44.413 40.152 ;
     RECT  44.305 10.656 44.453 13.32 ;
     RECT  44.389 35.136 44.476 37.416 ;
     RECT  44.453 10.752 44.665 13.32 ;
     RECT  44.021 14.4 44.665 15.864 ;
     RECT  43.549 6.528 44.701 7.368 ;
     RECT  43.909 2.592 44.869 3.672 ;
     RECT  44.701 6.528 45.109 8.04 ;
     RECT  45.109 6.528 45.157 8.52 ;
     RECT  44.195 42.24 45.349 42.264 ;
     RECT  45.097 4.944 45.493 4.968 ;
     RECT  43.949 44.112 45.565 44.952 ;
     RECT  44.869 2.352 45.608 3.672 ;
     RECT  45.493 4.704 45.608 4.968 ;
     RECT  45.157 6.24 45.608 8.52 ;
     RECT  45.601 9.504 45.608 9.528 ;
     RECT  44.665 10.752 45.608 15.864 ;
     RECT  44.345 18.144 45.608 20.904 ;
     RECT  44.345 22.032 45.608 33.96 ;
     RECT  44.476 35.232 45.608 37.416 ;
     RECT  45.493 38.784 45.608 38.808 ;
     RECT  44.413 39.84 45.608 40.152 ;
     RECT  45.349 41.376 45.608 42.264 ;
     RECT  45.565 44.064 45.608 44.952 ;
     RECT  45.608 2.148 45.712 45.372 ;
     RECT  45.712 2.418 45.904 45.102 ;
     RECT  45.904 39.84 46.019 41.352 ;
     RECT  46.019 40.128 46.045 41.352 ;
     RECT  45.904 37.344 46.073 37.368 ;
     RECT  45.904 42.576 46.109 42.792 ;
     RECT  45.904 43.872 46.217 44.952 ;
     RECT  45.904 21.936 46.259 28.488 ;
     RECT  45.904 4.128 46.361 20.616 ;
     RECT  46.361 7.776 46.505 20.616 ;
     RECT  46.505 14.736 46.613 20.616 ;
     RECT  46.613 15.456 46.649 20.616 ;
     RECT  46.045 40.128 46.721 40.44 ;
     RECT  46.649 15.456 46.757 18.264 ;
     RECT  46.259 21.936 46.793 25.8 ;
     RECT  46.361 4.128 46.829 6.696 ;
     RECT  46.505 7.776 46.829 13.368 ;
     RECT  46.109 42.576 46.865 42.6 ;
     RECT  46.829 10.848 46.901 13.368 ;
     RECT  46.793 23.664 46.901 25.8 ;
     RECT  45.904 38.688 46.933 38.712 ;
     RECT  45.904 30.192 47.005 36.216 ;
     RECT  46.901 12.528 47.009 13.368 ;
     RECT  46.933 38.016 47.02 38.712 ;
     RECT  47.005 30.192 47.045 36.456 ;
     RECT  46.721 40.272 47.077 40.44 ;
     RECT  46.829 4.128 47.085 4.152 ;
     RECT  46.217 43.872 47.123 44.472 ;
     RECT  47.045 32.544 47.141 36.456 ;
     RECT  47.141 32.544 47.18 36.504 ;
     RECT  47.085 3.984 47.189 4.152 ;
     RECT  47.18 32.544 47.261 36.648 ;
     RECT  47.039 41.664 47.267 41.688 ;
     RECT  46.649 19.392 47.329 20.616 ;
     RECT  46.259 26.832 47.333 28.488 ;
     RECT  46.793 21.936 47.405 21.96 ;
     RECT  47.261 36.192 47.405 36.648 ;
     RECT  47.045 30.192 47.441 31.56 ;
     RECT  46.901 24.576 47.473 25.8 ;
     RECT  47.333 26.832 47.473 26.856 ;
     RECT  47.009 12.768 47.509 13.368 ;
     RECT  47.509 12.768 47.513 14.184 ;
     RECT  47.123 43.872 47.516 44.136 ;
     RECT  47.329 19.392 47.549 20.664 ;
     RECT  46.757 16.032 47.585 18.264 ;
     RECT  46.829 7.776 47.621 9.816 ;
     RECT  47.513 14.16 47.621 14.184 ;
     RECT  47.585 17.04 47.621 18.264 ;
     RECT  47.473 24.576 47.765 26.856 ;
     RECT  47.516 43.152 47.765 44.136 ;
     RECT  47.333 27.84 47.797 28.488 ;
     RECT  47.621 17.04 47.801 18.216 ;
     RECT  47.549 20.112 47.801 20.664 ;
     RECT  47.801 20.112 47.837 20.136 ;
     RECT  47.405 36.624 47.869 36.648 ;
     RECT  47.801 18.192 47.873 18.216 ;
     RECT  47.765 24.576 47.873 26.76 ;
     RECT  47.441 30.192 47.873 30.792 ;
     RECT  47.02 38.688 47.905 38.712 ;
     RECT  47.801 17.04 47.909 17.064 ;
     RECT  47.797 27.84 47.909 28.536 ;
     RECT  47.621 8.208 47.941 9.816 ;
     RECT  46.901 10.848 47.941 11.112 ;
     RECT  47.765 43.152 47.945 43.944 ;
     RECT  46.829 5.904 47.987 6.696 ;
     RECT  47.941 8.208 47.987 11.112 ;
     RECT  47.077 40.272 48.013 40.584 ;
     RECT  47.513 12.768 48.017 12.936 ;
     RECT  47.261 32.544 48.017 34.776 ;
     RECT  47.869 36.624 48.017 37.272 ;
     RECT  47.987 10.464 48.028 10.92 ;
     RECT  47.941 21.12 48.053 21.144 ;
     RECT  47.189 3.984 48.085 4.008 ;
     RECT  47.909 28.464 48.089 28.536 ;
     RECT  47.987 8.208 48.125 8.904 ;
     RECT  47.873 25.296 48.125 26.76 ;
     RECT  47.873 30.768 48.125 30.792 ;
     RECT  48.017 37.248 48.125 37.272 ;
     RECT  48.013 39.792 48.125 40.584 ;
     RECT  47.945 43.92 48.125 43.944 ;
     RECT  48.017 32.784 48.161 32.808 ;
     RECT  48.125 40.272 48.193 40.584 ;
     RECT  45.904 2.64 48.233 2.664 ;
     RECT  48.028 10.848 48.233 10.92 ;
     RECT  48.017 12.912 48.233 12.936 ;
     RECT  48.125 25.296 48.233 25.32 ;
     RECT  48.193 40.272 48.236 41.496 ;
     RECT  48.236 40.272 48.277 42.072 ;
     RECT  48.085 3.936 48.305 4.008 ;
     RECT  48.089 28.464 48.305 28.488 ;
     RECT  48.017 34.032 48.305 34.776 ;
     RECT  48.277 40.272 48.323 42.792 ;
     RECT  48.125 8.88 48.341 8.904 ;
     RECT  48.323 40.272 48.377 41.496 ;
     RECT  48.377 40.272 48.449 41.016 ;
     RECT  48.233 10.848 48.593 10.872 ;
     RECT  48.305 34.032 48.593 34.056 ;
     RECT  48.524 37.584 48.611 37.608 ;
     RECT  48.449 40.992 48.629 41.016 ;
     RECT  48.323 42.768 48.629 42.792 ;
     RECT  47.905 38.688 48.657 38.76 ;
     RECT  47.987 6.672 48.773 6.696 ;
     RECT  48.657 38.736 48.773 38.76 ;
     RECT  48.305 3.936 49.097 3.96 ;
     RECT  50.641 7.728 50.677 7.752 ;
     RECT  50.173 20.304 50.677 20.328 ;
     RECT  50.173 22.752 50.677 22.776 ;
     RECT  50.677 15.84 50.713 16.296 ;
     RECT  50.677 17.472 50.713 21.144 ;
     RECT  50.677 22.32 50.713 25.176 ;
     RECT  50.677 26.4 50.713 30.072 ;
     RECT  50.713 15.456 51.685 30.072 ;
     RECT  50.677 31.632 51.685 34.056 ;
     RECT  50.677 7.728 51.721 13.848 ;
     RECT  51.685 15.456 51.721 34.056 ;
     RECT  51.721 7.008 51.756 7.032 ;
     RECT  51.721 7.032 51.804 7.728 ;
     RECT  51.721 7.728 51.756 7.752 ;
     RECT  51.721 7.752 51.804 8.16 ;
     RECT  51.721 8.16 51.756 8.184 ;
     RECT  51.721 8.184 51.804 8.544 ;
     RECT  51.721 8.544 51.756 8.568 ;
     RECT  51.721 8.568 51.804 8.976 ;
     RECT  51.721 8.976 51.756 9 ;
     RECT  51.721 9 51.804 9.36 ;
     RECT  51.721 9.36 51.756 9.384 ;
     RECT  51.721 9.384 51.804 9.792 ;
     RECT  51.721 9.792 51.756 9.816 ;
     RECT  51.721 9.816 51.804 10.176 ;
     RECT  51.721 10.176 51.756 10.2 ;
     RECT  51.721 10.2 51.804 10.608 ;
     RECT  51.721 10.608 51.756 10.632 ;
     RECT  51.721 10.632 51.804 10.992 ;
     RECT  51.721 10.992 51.756 11.016 ;
     RECT  51.721 11.016 51.804 11.376 ;
     RECT  51.721 11.376 51.756 11.4 ;
     RECT  51.721 11.4 51.804 11.808 ;
     RECT  51.721 11.808 51.756 11.832 ;
     RECT  51.721 11.832 51.804 12.192 ;
     RECT  51.721 12.192 51.756 12.216 ;
     RECT  51.721 12.216 51.804 12.624 ;
     RECT  51.721 12.624 51.756 12.648 ;
     RECT  51.721 12.648 51.804 13.008 ;
     RECT  51.721 13.008 51.756 13.032 ;
     RECT  51.721 13.032 51.804 13.44 ;
     RECT  51.721 13.44 51.756 13.464 ;
     RECT  51.721 13.464 51.804 13.824 ;
     RECT  51.721 13.824 51.756 13.848 ;
     RECT  51.721 13.848 51.804 14.208 ;
     RECT  51.721 14.208 51.756 14.232 ;
     RECT  51.721 14.232 51.804 14.64 ;
     RECT  51.721 14.64 51.756 14.664 ;
     RECT  51.721 14.664 51.804 15.024 ;
     RECT  51.721 15.024 51.756 15.048 ;
     RECT  51.721 15.048 51.804 15.456 ;
     RECT  51.721 15.456 51.756 15.48 ;
     RECT  51.721 15.48 51.804 15.84 ;
     RECT  51.721 15.84 51.756 15.864 ;
     RECT  51.721 15.864 51.804 16.272 ;
     RECT  51.721 16.272 51.756 16.296 ;
     RECT  51.721 16.296 51.804 16.656 ;
     RECT  51.721 16.656 51.756 16.68 ;
     RECT  51.721 16.68 51.804 17.088 ;
     RECT  51.721 17.088 51.756 17.112 ;
     RECT  51.721 17.112 51.804 17.472 ;
     RECT  51.721 17.472 51.756 17.496 ;
     RECT  51.721 17.496 51.804 17.856 ;
     RECT  51.721 17.856 51.756 17.88 ;
     RECT  51.721 17.88 51.804 18.288 ;
     RECT  51.721 18.288 51.756 18.312 ;
     RECT  51.721 18.312 51.804 18.672 ;
     RECT  51.721 18.672 51.756 18.696 ;
     RECT  51.721 18.696 51.804 19.104 ;
     RECT  51.721 19.104 51.756 19.128 ;
     RECT  51.721 19.128 51.804 19.488 ;
     RECT  51.721 19.488 51.756 19.512 ;
     RECT  51.721 19.512 51.804 19.92 ;
     RECT  51.721 19.92 51.756 19.944 ;
     RECT  51.721 19.944 51.804 20.304 ;
     RECT  51.721 20.304 51.756 20.328 ;
     RECT  51.721 20.328 51.804 20.688 ;
     RECT  51.721 20.688 51.756 20.712 ;
     RECT  51.721 20.712 51.804 21.12 ;
     RECT  51.721 21.12 51.756 21.144 ;
     RECT  51.721 21.144 51.804 21.504 ;
     RECT  51.721 21.504 51.756 21.528 ;
     RECT  51.721 21.528 51.804 21.936 ;
     RECT  51.721 21.936 51.756 21.96 ;
     RECT  51.721 21.96 51.804 22.32 ;
     RECT  51.721 22.32 51.756 22.344 ;
     RECT  51.721 22.344 51.804 22.752 ;
     RECT  51.721 22.752 51.756 22.776 ;
     RECT  51.721 22.776 51.804 23.136 ;
     RECT  51.721 23.136 51.756 23.16 ;
     RECT  51.721 23.16 51.804 23.568 ;
     RECT  51.721 23.568 51.756 23.592 ;
     RECT  51.721 23.592 51.804 23.952 ;
     RECT  51.721 23.952 51.756 23.976 ;
     RECT  51.721 23.976 51.804 24.336 ;
     RECT  51.721 24.336 51.756 24.36 ;
     RECT  51.721 24.36 51.804 24.768 ;
     RECT  51.721 24.768 51.756 24.792 ;
     RECT  51.721 24.792 51.804 25.152 ;
     RECT  51.721 25.152 51.756 25.176 ;
     RECT  51.721 25.176 51.804 25.584 ;
     RECT  51.721 25.584 51.756 25.608 ;
     RECT  51.721 25.608 51.804 25.968 ;
     RECT  51.721 25.968 51.756 25.992 ;
     RECT  51.721 25.992 51.804 26.4 ;
     RECT  51.721 26.4 51.756 26.424 ;
     RECT  51.721 26.424 51.804 26.784 ;
     RECT  51.721 26.784 51.756 26.808 ;
     RECT  51.721 26.808 51.804 27.168 ;
     RECT  51.721 27.168 51.756 27.192 ;
     RECT  51.721 27.192 51.804 27.6 ;
     RECT  51.721 27.6 51.756 27.624 ;
     RECT  51.721 27.624 51.804 27.984 ;
     RECT  51.721 27.984 51.756 28.008 ;
     RECT  51.721 28.008 51.804 28.416 ;
     RECT  51.721 28.416 51.756 28.44 ;
     RECT  51.721 28.44 51.804 28.8 ;
     RECT  51.721 28.8 51.756 28.824 ;
     RECT  51.721 28.824 51.804 29.232 ;
     RECT  51.721 29.232 51.756 29.256 ;
     RECT  51.721 29.256 51.804 29.616 ;
     RECT  51.721 29.616 51.756 29.64 ;
     RECT  51.721 29.64 51.804 30.048 ;
     RECT  51.721 30.048 51.756 30.072 ;
     RECT  51.721 30.072 51.804 30.432 ;
     RECT  51.721 30.432 51.756 30.456 ;
     RECT  51.721 30.456 51.804 30.816 ;
     RECT  51.721 30.816 51.756 30.84 ;
     RECT  51.721 30.84 51.804 31.248 ;
     RECT  51.721 31.248 51.756 31.272 ;
     RECT  51.721 31.272 51.804 31.632 ;
     RECT  51.721 31.632 51.756 31.656 ;
     RECT  51.721 31.656 51.804 32.064 ;
     RECT  51.721 32.064 51.756 32.088 ;
     RECT  51.721 32.088 51.804 32.448 ;
     RECT  51.721 32.448 51.756 32.472 ;
     RECT  51.721 32.472 51.804 32.88 ;
     RECT  51.721 32.88 51.756 32.904 ;
     RECT  51.721 32.904 51.804 33.264 ;
     RECT  51.721 33.264 51.756 33.288 ;
     RECT  51.721 33.288 51.804 34.032 ;
     RECT  51.721 34.032 51.756 34.056 ;
    LAYER M5 ;
     RECT  24.864 0.085 24.888 2.137 ;
     RECT  2.4 2.137 2.52 2.151 ;
     RECT  7.8 2.137 7.92 2.151 ;
     RECT  13.2 2.137 13.32 2.151 ;
     RECT  18.6 2.137 18.72 2.151 ;
     RECT  29.4 2.137 29.52 2.151 ;
     RECT  34.8 2.137 34.92 2.151 ;
     RECT  40.2 2.137 40.32 2.151 ;
     RECT  45.6 2.137 45.72 2.151 ;
     RECT  24 2.137 24.888 2.245 ;
     RECT  34.8 2.151 35.112 2.245 ;
     RECT  45.6 2.151 45.912 2.341 ;
     RECT  29.4 2.151 29.712 2.629 ;
     RECT  29.4 2.629 30.072 2.821 ;
     RECT  31.296 2.245 31.32 2.821 ;
     RECT  44.88 2.341 45.912 2.915 ;
     RECT  13.2 2.151 13.512 3.013 ;
     RECT  34.8 2.245 35.208 3.349 ;
     RECT  20.88 2.869 20.904 3.443 ;
     RECT  29.4 2.821 31.32 3.443 ;
     RECT  23.328 2.245 24.888 3.635 ;
     RECT  15.84 2.725 15.864 3.683 ;
     RECT  23.904 3.635 24.888 3.683 ;
     RECT  41.568 2.773 41.592 3.683 ;
     RECT  40.2 2.151 40.512 3.685 ;
     RECT  11.424 2.293 11.448 3.875 ;
     RECT  2.4 2.151 2.712 3.925 ;
     RECT  18.6 2.151 18.912 3.925 ;
     RECT  38.784 3.397 38.808 3.971 ;
     RECT  7.8 2.151 8.112 3.973 ;
     RECT  47.136 2.629 47.16 4.019 ;
     RECT  29.4 3.443 30.792 4.259 ;
     RECT  12.816 3.013 13.512 4.403 ;
     RECT  37.44 2.677 37.464 4.501 ;
     RECT  45.6 2.915 45.912 4.501 ;
     RECT  37.008 4.501 37.464 4.547 ;
     RECT  2.4 3.925 2.856 4.595 ;
     RECT  13.2 4.403 13.512 4.645 ;
     RECT  14.496 2.821 14.52 4.645 ;
     RECT  7.392 3.973 8.112 4.837 ;
     RECT  30.816 4.885 30.84 5.171 ;
     RECT  4.368 2.821 4.392 5.221 ;
     RECT  4.224 5.221 4.392 5.267 ;
     RECT  13.2 4.645 14.52 5.315 ;
     RECT  13.2 5.315 13.608 5.459 ;
     RECT  24 3.683 24.888 5.461 ;
     RECT  34.8 3.349 35.256 5.605 ;
     RECT  40.08 3.685 40.512 5.653 ;
     RECT  26.784 3.157 26.808 5.699 ;
     RECT  43.392 4.549 43.416 5.747 ;
     RECT  7.392 4.837 8.568 6.035 ;
     RECT  34.368 5.605 35.256 6.035 ;
     RECT  15.984 4.549 16.008 6.181 ;
     RECT  22.752 4.501 22.776 6.229 ;
     RECT  45.6 4.501 46.008 6.229 ;
     RECT  37.008 4.547 37.032 6.323 ;
     RECT  7.488 6.035 8.568 6.851 ;
     RECT  38.976 6.229 39 6.899 ;
     RECT  23.904 5.461 24.888 6.947 ;
     RECT  29.4 4.259 29.832 6.949 ;
     RECT  29.088 6.949 29.832 6.995 ;
     RECT  18.6 3.925 19.176 7.091 ;
     RECT  34.368 6.035 35.208 7.189 ;
     RECT  33.504 7.189 35.208 7.235 ;
     RECT  45.168 6.229 46.008 7.285 ;
     RECT  26.544 6.229 26.568 7.379 ;
     RECT  45.024 7.285 46.008 7.381 ;
     RECT  45.024 7.381 46.056 7.427 ;
     RECT  22.704 6.229 22.776 7.429 ;
     RECT  15.984 6.181 16.968 7.475 ;
     RECT  27.648 6.709 27.672 7.619 ;
     RECT  4.224 5.267 4.248 7.621 ;
     RECT  21.168 5.557 21.192 7.909 ;
     RECT  22.176 7.429 22.776 7.909 ;
     RECT  24 6.947 24.888 7.909 ;
     RECT  4.032 7.621 4.248 7.957 ;
     RECT  38.736 7.381 38.76 8.003 ;
     RECT  16.944 7.475 16.968 8.149 ;
     RECT  18.6 7.091 18.912 8.149 ;
     RECT  47.952 5.893 47.976 8.243 ;
     RECT  29.088 6.995 29.712 8.339 ;
     RECT  13.2 5.459 13.512 8.485 ;
     RECT  45.168 7.427 46.056 8.485 ;
     RECT  16.944 8.149 18.912 8.675 ;
     RECT  33.504 7.235 33.528 8.675 ;
     RECT  40.032 5.653 40.512 8.677 ;
     RECT  4.032 7.957 4.536 8.723 ;
     RECT  39.888 8.677 40.512 8.819 ;
     RECT  2.4 4.595 2.712 8.821 ;
     RECT  4.512 8.723 4.536 9.011 ;
     RECT  13.2 8.485 13.752 9.061 ;
     RECT  16.944 8.675 16.968 9.061 ;
     RECT  34.8 7.235 35.208 9.061 ;
     RECT  45.12 8.485 46.056 9.061 ;
     RECT  12.624 9.061 13.752 9.107 ;
     RECT  6.768 7.381 6.792 9.155 ;
     RECT  11.424 7.957 11.448 9.155 ;
     RECT  24 7.909 25.128 9.251 ;
     RECT  18.6 8.675 18.912 9.349 ;
     RECT  36.624 7.861 36.648 9.685 ;
     RECT  45.12 9.061 46.2 9.827 ;
     RECT  36.48 9.685 36.648 9.877 ;
     RECT  37.68 9.685 37.704 9.877 ;
     RECT  34.176 9.061 35.208 9.923 ;
     RECT  12.624 9.107 13.512 9.925 ;
     RECT  16.08 9.061 16.968 10.019 ;
     RECT  18.6 9.349 19.464 10.067 ;
     RECT  27.888 8.485 27.912 10.067 ;
     RECT  16.944 10.019 16.968 10.261 ;
     RECT  21.168 7.909 22.776 10.307 ;
     RECT  34.176 9.923 35.112 10.595 ;
     RECT  36.48 9.877 37.704 10.595 ;
     RECT  2.4 8.821 3.096 10.789 ;
     RECT  12.528 9.925 13.512 10.883 ;
     RECT  26.16 8.917 26.184 10.883 ;
     RECT  2.4 10.789 3.144 10.981 ;
     RECT  47.952 9.637 47.976 11.123 ;
     RECT  18.6 10.067 18.912 11.125 ;
     RECT  16.944 10.261 17.304 11.171 ;
     RECT  21.36 10.307 22.776 11.171 ;
     RECT  45.12 9.827 46.152 11.221 ;
     RECT  2.4 10.981 4.104 11.413 ;
     RECT  37.104 10.595 37.704 11.459 ;
     RECT  29.4 8.339 29.712 11.701 ;
     RECT  45.024 11.221 46.152 11.795 ;
     RECT  33.504 11.269 33.528 11.845 ;
     RECT  34.8 10.595 35.112 11.941 ;
     RECT  40.08 8.819 40.512 11.941 ;
     RECT  45.024 11.795 46.008 12.083 ;
     RECT  21.36 11.171 22.728 12.131 ;
     RECT  2.4 11.413 4.872 12.179 ;
     RECT  37.104 11.459 37.512 12.419 ;
     RECT  18.6 11.125 19.032 12.421 ;
     RECT  37.488 12.419 37.512 12.469 ;
     RECT  6.432 11.173 6.456 12.515 ;
     RECT  26.112 11.029 26.136 12.563 ;
     RECT  18.48 12.421 19.032 12.611 ;
     RECT  17.28 11.171 17.304 12.709 ;
     RECT  32.496 5.269 32.52 12.709 ;
     RECT  16.56 12.709 17.304 12.755 ;
     RECT  31.872 12.709 32.52 12.755 ;
     RECT  9.648 11.173 9.672 12.853 ;
     RECT  40.08 11.941 41.064 12.899 ;
     RECT  33.504 11.845 33.672 12.995 ;
     RECT  24 9.251 24.888 13.045 ;
     RECT  33.648 12.995 33.672 13.235 ;
     RECT  9.648 12.853 10.344 13.283 ;
     RECT  11.712 12.853 11.736 13.285 ;
     RECT  11.424 13.285 11.736 13.331 ;
     RECT  37.488 12.469 37.56 13.331 ;
     RECT  13.2 10.883 13.512 13.333 ;
     RECT  18.6 12.611 19.032 13.333 ;
     RECT  40.08 12.899 40.512 13.379 ;
     RECT  29.4 11.701 29.832 13.427 ;
     RECT  23.376 13.045 24.888 13.477 ;
     RECT  7.8 6.851 8.568 13.765 ;
     RECT  9.648 13.283 9.672 13.765 ;
     RECT  2.4 12.179 4.104 13.811 ;
     RECT  21.36 12.131 22.2 13.861 ;
     RECT  20.688 13.861 22.2 13.907 ;
     RECT  18.6 13.333 19.704 13.909 ;
     RECT  18.48 13.909 19.704 13.955 ;
     RECT  26.736 13.093 26.76 13.957 ;
     RECT  7.8 13.765 9.672 14.099 ;
     RECT  34.8 11.941 35.352 14.099 ;
     RECT  3.984 13.811 4.104 14.197 ;
     RECT  5.712 13.477 5.736 14.197 ;
     RECT  23.376 13.477 25.656 14.339 ;
     RECT  16.56 12.755 16.584 14.387 ;
     RECT  45.024 12.083 45.912 14.389 ;
     RECT  3.984 14.197 5.736 14.531 ;
     RECT  24 14.339 25.656 14.677 ;
     RECT  26.736 13.957 27.72 14.677 ;
     RECT  13.2 13.333 13.608 14.723 ;
     RECT  24 14.677 27.72 14.723 ;
     RECT  31.872 12.755 31.896 14.773 ;
     RECT  27.696 14.723 27.72 14.819 ;
     RECT  5.088 14.531 5.112 14.867 ;
     RECT  18.48 13.955 19.032 14.867 ;
     RECT  7.8 14.099 8.808 14.915 ;
     RECT  11.424 13.331 11.448 14.915 ;
     RECT  31.776 14.773 31.896 14.915 ;
     RECT  22.176 13.907 22.2 14.963 ;
     RECT  44.88 14.389 45.912 15.059 ;
     RECT  20.688 13.907 20.712 15.157 ;
     RECT  40.2 13.379 40.512 15.253 ;
     RECT  45.024 15.059 45.912 15.349 ;
     RECT  39.888 15.253 40.512 15.443 ;
     RECT  24 14.723 26.376 15.491 ;
     RECT  9.888 15.253 9.912 16.019 ;
     RECT  42.192 13.621 42.216 16.019 ;
     RECT  20.592 15.157 20.712 16.213 ;
     RECT  20.592 16.213 21.672 16.405 ;
     RECT  18.6 14.867 19.032 16.453 ;
     RECT  33.648 14.773 33.672 16.595 ;
     RECT  43.584 15.829 43.608 16.595 ;
     RECT  16.56 15.637 16.584 16.597 ;
     RECT  16.56 16.597 17.112 16.643 ;
     RECT  7.8 14.915 8.472 16.691 ;
     RECT  45.024 15.349 46.392 17.075 ;
     RECT  37.488 13.331 37.512 17.077 ;
     RECT  14.832 16.501 14.856 17.123 ;
     RECT  20.592 16.405 21.72 17.171 ;
     RECT  34.8 14.099 35.112 17.173 ;
     RECT  31.872 14.915 31.896 17.219 ;
     RECT  3.984 14.531 4.104 17.315 ;
     RECT  24 15.491 24.888 17.317 ;
     RECT  20.592 17.171 20.616 17.363 ;
     RECT  11.136 16.501 11.16 17.459 ;
     RECT  23.904 17.317 24.888 17.459 ;
     RECT  7.8 16.691 8.232 17.651 ;
     RECT  16.704 16.643 17.112 17.651 ;
     RECT  37.488 17.077 38.088 17.749 ;
     RECT  18.6 16.453 19.416 17.941 ;
     RECT  40.2 15.443 40.512 18.229 ;
     RECT  37.344 17.749 38.088 18.275 ;
     RECT  37.344 18.275 37.368 18.419 ;
     RECT  28.368 16.885 28.392 18.565 ;
     RECT  29.4 13.427 29.712 18.565 ;
     RECT  13.2 14.723 13.512 18.757 ;
     RECT  43.92 18.181 43.944 18.803 ;
     RECT  12.864 18.757 13.512 19.093 ;
     RECT  18.6 17.941 19.704 19.237 ;
     RECT  21.648 17.171 21.72 19.237 ;
     RECT  22.8 17.029 22.824 19.237 ;
     RECT  21.648 19.237 22.824 19.283 ;
     RECT  2.4 13.811 2.712 19.333 ;
     RECT  21.696 19.283 22.824 19.523 ;
     RECT  12.432 19.093 13.512 19.621 ;
     RECT  45.024 17.075 45.912 19.621 ;
     RECT  40.08 18.229 40.512 19.765 ;
     RECT  2.4 19.333 2.952 19.811 ;
     RECT  39.12 19.765 40.512 19.811 ;
     RECT  33.84 17.173 35.112 19.813 ;
     RECT  12.096 19.621 13.512 19.861 ;
     RECT  14.688 18.757 14.712 19.909 ;
     RECT  24 17.459 24.888 19.909 ;
     RECT  40.2 19.811 40.512 19.909 ;
     RECT  11.232 19.861 13.512 19.955 ;
     RECT  16.704 17.651 16.728 20.003 ;
     RECT  18.6 19.237 20.424 20.051 ;
     RECT  7.8 17.651 8.112 20.149 ;
     RECT  45.024 19.621 46.248 20.195 ;
     RECT  7.392 20.149 8.376 20.245 ;
     RECT  4.08 17.315 4.104 20.291 ;
     RECT  6.864 20.245 8.376 20.339 ;
     RECT  14.688 19.909 14.76 20.339 ;
     RECT  23.424 19.909 24.888 20.485 ;
     RECT  26.352 15.491 26.376 20.485 ;
     RECT  23.424 20.485 25.128 20.579 ;
     RECT  39.12 19.811 39.144 20.579 ;
     RECT  45.024 20.195 45.912 20.627 ;
     RECT  30.72 19.909 30.744 20.867 ;
     RECT  17.088 20.485 17.112 21.109 ;
     RECT  16.992 21.109 17.112 21.155 ;
     RECT  26.352 20.485 27.336 21.155 ;
     RECT  33.84 19.813 35.352 21.155 ;
     RECT  6.864 20.339 8.112 21.395 ;
     RECT  28.368 18.565 29.712 21.395 ;
     RECT  29.4 21.395 29.712 21.541 ;
     RECT  14.736 20.339 14.76 21.637 ;
     RECT  21.696 19.523 22.104 21.683 ;
     RECT  43.632 19.621 43.656 21.683 ;
     RECT  24 20.579 25.128 21.971 ;
     RECT  45.6 20.627 45.912 22.021 ;
     RECT  16.992 21.155 17.016 22.163 ;
     RECT  2.4 19.811 2.712 22.165 ;
     RECT  3.936 21.061 3.96 22.165 ;
     RECT  14.64 21.637 14.76 22.213 ;
     RECT  34.8 21.155 35.352 22.213 ;
     RECT  11.232 19.955 12.12 22.307 ;
     RECT  40.2 19.909 40.632 22.451 ;
     RECT  34.704 22.213 35.352 22.499 ;
     RECT  40.2 22.451 40.512 22.549 ;
     RECT  26.352 21.155 26.376 22.645 ;
     RECT  2.4 22.165 3.96 22.693 ;
     RECT  14.64 22.213 14.808 22.739 ;
     RECT  2.4 22.693 4.2 22.741 ;
     RECT  22.08 21.683 22.104 22.741 ;
     RECT  32.496 21.301 32.52 22.741 ;
     RECT  33.648 22.213 33.672 22.741 ;
     RECT  32.496 22.741 33.672 22.787 ;
     RECT  45.216 22.021 45.912 22.787 ;
     RECT  40.08 22.549 40.512 22.789 ;
     RECT  28.368 21.395 28.392 22.835 ;
     RECT  29.4 21.541 30.552 22.981 ;
     RECT  11.232 22.307 11.256 23.171 ;
     RECT  18.6 20.051 19.704 23.219 ;
     RECT  34.704 22.499 35.112 23.267 ;
     RECT  2.4 22.741 4.68 23.317 ;
     RECT  13.2 19.955 13.512 23.317 ;
     RECT  24 21.971 24.888 23.411 ;
     RECT  33.024 22.787 33.048 23.411 ;
     RECT  14.784 22.739 14.808 23.555 ;
     RECT  39.456 22.789 40.512 23.555 ;
     RECT  29.136 22.981 30.552 23.651 ;
     RECT  24 23.411 24.504 23.699 ;
     RECT  26.352 22.645 27.336 23.843 ;
     RECT  12.768 23.317 13.512 23.893 ;
     RECT  2.4 23.317 5.448 23.941 ;
     RECT  39.84 23.555 40.512 23.941 ;
     RECT  41.568 22.741 41.592 23.941 ;
     RECT  9.12 23.989 9.144 24.131 ;
     RECT  21.648 22.741 22.104 24.323 ;
     RECT  39.84 23.941 41.592 24.419 ;
     RECT  12.768 23.893 14.232 24.467 ;
     RECT  2.4 23.941 6.072 24.515 ;
     RECT  24 23.699 24.408 24.515 ;
     RECT  41.568 24.419 41.592 24.515 ;
     RECT  34.8 23.267 35.112 24.517 ;
     RECT  2.4 24.515 5.448 24.563 ;
     RECT  45.6 22.787 45.912 24.565 ;
     RECT  26.352 23.843 27.096 24.755 ;
     RECT  29.4 23.651 30.552 24.755 ;
     RECT  26.352 24.755 26.616 24.947 ;
     RECT  45.6 24.565 46.584 25.091 ;
     RECT  43.728 24.373 43.752 25.139 ;
     RECT  13.2 24.467 14.232 25.141 ;
     RECT  34.8 24.517 35.448 25.283 ;
     RECT  16.56 24.373 16.584 25.285 ;
     RECT  38.16 23.893 38.184 25.285 ;
     RECT  39.84 24.419 40.512 25.285 ;
     RECT  21.648 24.323 21.672 25.427 ;
     RECT  13.2 25.141 14.616 25.573 ;
     RECT  38.16 25.285 40.512 25.573 ;
     RECT  7.8 21.395 8.112 25.621 ;
     RECT  10.944 23.893 10.968 25.621 ;
     RECT  10.944 25.621 11.064 25.667 ;
     RECT  12.576 25.573 14.616 25.715 ;
     RECT  32.352 24.469 32.376 25.765 ;
     RECT  7.68 25.621 8.112 25.813 ;
     RECT  38.064 25.573 40.512 26.003 ;
     RECT  16.56 25.285 16.968 26.197 ;
     RECT  26.352 24.947 26.376 26.197 ;
     RECT  2.4 24.563 4.92 26.291 ;
     RECT  12.576 25.715 13.512 26.387 ;
     RECT  33.648 25.237 33.672 26.437 ;
     RECT  34.8 25.283 35.112 26.437 ;
     RECT  7.68 25.813 8.424 26.531 ;
     RECT  14.592 25.715 14.616 26.531 ;
     RECT  11.04 25.667 11.064 26.579 ;
     RECT  39.072 26.003 40.512 26.579 ;
     RECT  12.768 26.387 13.512 26.677 ;
     RECT  30.72 25.189 30.744 26.723 ;
     RECT  15.936 26.197 16.968 26.771 ;
     RECT  2.4 26.291 3.96 26.819 ;
     RECT  16.704 26.771 16.968 26.819 ;
     RECT  36.816 26.869 36.84 27.013 ;
     RECT  38.064 26.003 38.088 27.013 ;
     RECT  36.816 27.013 38.088 27.059 ;
     RECT  32.208 25.765 32.376 27.109 ;
     RECT  32.208 27.109 32.472 27.155 ;
     RECT  3.936 26.819 3.96 27.203 ;
     RECT  37.632 27.059 38.088 27.203 ;
     RECT  25.488 26.197 26.376 27.347 ;
     RECT  39.312 26.579 40.512 27.395 ;
     RECT  18.6 23.219 18.912 27.589 ;
     RECT  33.648 26.437 35.112 27.635 ;
     RECT  12.768 26.677 13.896 27.877 ;
     RECT  34.176 27.635 35.112 27.877 ;
     RECT  12.768 27.877 14.856 27.923 ;
     RECT  34.176 27.877 35.352 27.923 ;
     RECT  7.68 26.531 8.112 27.973 ;
     RECT  32.448 27.155 32.472 28.163 ;
     RECT  2.4 26.819 2.712 28.453 ;
     RECT  27.936 27.877 27.96 28.499 ;
     RECT  14.832 27.923 14.856 28.501 ;
     RECT  21.264 28.405 21.288 28.547 ;
     RECT  42.48 27.301 42.504 28.547 ;
     RECT  12.768 27.923 13.512 28.741 ;
     RECT  39.504 27.395 40.512 28.931 ;
     RECT  34.464 27.923 35.352 29.029 ;
     RECT  18.6 27.589 19.032 29.075 ;
     RECT  10.176 27.925 10.2 29.123 ;
     RECT  33.552 29.029 35.352 29.173 ;
     RECT  14.832 28.501 15.144 29.269 ;
     RECT  16.704 26.819 16.728 29.269 ;
     RECT  14.832 29.269 16.728 29.411 ;
     RECT  22.752 28.789 22.776 29.411 ;
     RECT  14.928 29.411 16.728 29.603 ;
     RECT  14.928 29.603 15.144 29.699 ;
     RECT  24 24.515 24.312 29.749 ;
     RECT  19.92 29.605 19.944 29.797 ;
     RECT  33.552 29.173 35.736 29.891 ;
     RECT  43.92 27.253 43.944 29.989 ;
     RECT  39.6 28.931 40.512 30.035 ;
     RECT  43.92 29.989 44.04 30.035 ;
     RECT  14.928 29.699 15.096 30.083 ;
     RECT  19.92 29.797 20.328 30.179 ;
     RECT  27.888 29.509 27.912 30.275 ;
     RECT  12.528 28.741 13.512 30.371 ;
     RECT  15.072 30.083 15.096 30.419 ;
     RECT  34.464 29.891 35.736 30.563 ;
     RECT  18.6 29.075 18.912 30.565 ;
     RECT  19.92 30.179 19.944 30.565 ;
     RECT  18.6 30.565 19.944 30.611 ;
     RECT  44.016 30.035 44.04 30.709 ;
     RECT  18.6 30.611 19.704 30.851 ;
     RECT  44.016 30.709 44.328 30.851 ;
     RECT  16.704 29.603 16.728 30.949 ;
     RECT  24 29.749 24.552 30.949 ;
     RECT  29.4 24.755 29.712 31.237 ;
     RECT  34.464 30.563 35.592 31.331 ;
     RECT  30.96 30.421 30.984 31.333 ;
     RECT  30.96 31.333 31.896 31.379 ;
     RECT  44.064 30.851 44.328 31.477 ;
     RECT  7.584 27.973 8.112 31.811 ;
     RECT  39.84 30.035 40.512 31.813 ;
     RECT  42.72 29.365 42.744 32.243 ;
     RECT  39.84 31.813 41.064 32.483 ;
     RECT  24 30.949 25.08 32.915 ;
     RECT  28.848 31.237 29.712 33.013 ;
     RECT  16.704 30.949 17.352 33.059 ;
     RECT  28.8 33.013 29.712 33.253 ;
     RECT  30.816 32.437 30.84 33.253 ;
     RECT  28.8 33.253 30.84 33.299 ;
     RECT  28.8 33.299 30.312 33.587 ;
     RECT  37.632 30.949 37.656 33.683 ;
     RECT  42.144 33.013 42.168 33.731 ;
     RECT  44.064 31.477 44.568 33.731 ;
     RECT  39.84 32.483 40.512 33.925 ;
     RECT  45.6 25.091 46.248 33.925 ;
     RECT  44.16 33.731 44.568 33.971 ;
     RECT  39.84 33.925 41.016 34.069 ;
     RECT  21.12 31.333 21.144 34.355 ;
     RECT  6.624 32.917 6.648 34.499 ;
     RECT  7.8 31.811 8.112 34.741 ;
     RECT  9.168 31.765 9.192 34.741 ;
     RECT  34.464 31.331 35.112 34.741 ;
     RECT  31.872 31.379 31.896 34.835 ;
     RECT  34.464 34.741 35.88 34.835 ;
     RECT  16.704 33.059 16.728 34.883 ;
     RECT  34.512 34.835 35.88 34.883 ;
     RECT  39.36 34.069 41.016 34.885 ;
     RECT  7.8 34.741 9.192 35.027 ;
     RECT  26.352 27.347 26.376 35.027 ;
     RECT  33.216 34.405 33.24 35.027 ;
     RECT  28.8 33.587 29.712 35.077 ;
     RECT  44.16 33.971 44.424 35.171 ;
     RECT  7.8 35.027 8.112 35.269 ;
     RECT  22.752 32.773 22.776 35.269 ;
     RECT  39.264 34.885 41.016 35.269 ;
     RECT  2.4 28.453 3.672 35.317 ;
     RECT  13.2 30.371 13.512 35.317 ;
     RECT  12 35.269 12.024 35.939 ;
     RECT  34.512 34.883 35.352 36.035 ;
     RECT  22.608 35.269 22.776 36.083 ;
     RECT  45.6 33.925 47.208 36.227 ;
     RECT  25.296 34.741 25.32 36.275 ;
     RECT  39.264 35.269 41.64 36.275 ;
     RECT  37.152 36.133 37.176 36.419 ;
     RECT  45.6 36.227 45.912 36.421 ;
     RECT  28.512 35.077 29.712 36.467 ;
     RECT  47.184 36.227 47.208 36.515 ;
     RECT  18.6 30.851 18.912 36.901 ;
     RECT  17.04 35.317 17.064 36.949 ;
     RECT  2.4 35.317 4.392 37.043 ;
     RECT  13.2 35.317 13.992 37.043 ;
     RECT  17.04 36.949 17.112 37.045 ;
     RECT  16.992 37.045 17.112 37.091 ;
     RECT  22.752 36.083 22.776 37.091 ;
     RECT  40.2 36.275 41.64 37.091 ;
     RECT  2.4 37.043 3.432 37.715 ;
     RECT  9.168 35.027 9.192 37.909 ;
     RECT  13.2 37.043 13.608 38.003 ;
     RECT  40.2 37.091 41.016 38.005 ;
     RECT  47.232 36.613 47.256 38.005 ;
     RECT  9.12 37.909 9.192 38.197 ;
     RECT  9.12 38.197 9.672 38.531 ;
     RECT  34.512 36.035 35.112 38.677 ;
     RECT  15.456 37.573 15.48 38.723 ;
     RECT  46.944 38.005 47.256 38.723 ;
     RECT  48.576 37.573 48.6 38.723 ;
     RECT  7.68 35.269 8.112 38.725 ;
     RECT  18.6 36.901 19.416 38.819 ;
     RECT  45.504 36.421 45.912 38.819 ;
     RECT  6.96 38.725 8.112 38.867 ;
     RECT  9.12 38.531 9.144 39.107 ;
     RECT  18.6 38.819 18.912 39.205 ;
     RECT  16.992 37.091 17.016 39.251 ;
     RECT  27.456 38.149 27.48 39.251 ;
     RECT  11.52 38.197 11.544 39.253 ;
     RECT  42.528 38.677 42.552 39.395 ;
     RECT  29.4 36.467 29.712 39.589 ;
     RECT  39.936 38.005 41.016 39.637 ;
     RECT  45.6 38.819 45.912 39.829 ;
     RECT  34.176 38.677 35.112 39.877 ;
     RECT  22.992 38.677 23.016 40.019 ;
     RECT  14.784 38.965 14.808 40.451 ;
     RECT  34.08 39.877 35.112 40.595 ;
     RECT  31.344 39.877 31.368 40.789 ;
     RECT  31.344 40.789 31.896 40.835 ;
     RECT  7.8 38.867 8.112 40.981 ;
     RECT  11.424 39.253 11.544 41.075 ;
     RECT  45.6 39.829 46.008 41.363 ;
     RECT  29.04 39.589 29.712 41.605 ;
     RECT  47.232 38.723 47.256 41.653 ;
     RECT  47.088 41.653 47.256 41.699 ;
     RECT  26.112 40.693 26.136 41.795 ;
     RECT  31.872 40.835 31.896 41.939 ;
     RECT  5.472 38.485 5.496 42.085 ;
     RECT  5.136 42.085 5.496 42.227 ;
     RECT  28.656 41.605 29.712 42.227 ;
     RECT  7.392 40.981 8.112 42.323 ;
     RECT  44.16 35.171 44.184 42.565 ;
     RECT  24 32.915 24.312 42.661 ;
     RECT  43.344 42.565 44.184 42.707 ;
     RECT  37.2 41.797 37.224 42.803 ;
     RECT  48.288 40.981 48.312 42.803 ;
     RECT  44.16 42.707 44.184 42.851 ;
     RECT  47.088 41.699 47.112 43.141 ;
     RECT  34.512 40.595 35.112 43.235 ;
     RECT  11.52 41.075 11.544 43.379 ;
     RECT  24 42.661 25.032 43.525 ;
     RECT  29.4 42.227 29.712 43.669 ;
     RECT  20.16 42.661 20.184 43.717 ;
     RECT  19.968 43.717 20.184 43.763 ;
     RECT  18.48 39.205 18.912 43.813 ;
     RECT  34.8 43.235 35.112 43.813 ;
     RECT  45.6 41.363 45.912 43.861 ;
     RECT  47.088 43.141 47.592 43.955 ;
     RECT  23.904 43.525 25.032 44.099 ;
     RECT  42.24 42.997 42.264 44.099 ;
     RECT  34.8 43.813 35.88 44.149 ;
     RECT  37.152 43.141 37.176 44.149 ;
     RECT  39.888 39.637 41.016 44.195 ;
     RECT  28.848 43.669 29.712 44.197 ;
     RECT  28.176 44.197 29.712 44.243 ;
     RECT  33.024 43.285 33.048 44.387 ;
     RECT  5.136 42.227 5.16 44.483 ;
     RECT  18.192 43.813 18.912 44.483 ;
     RECT  31.104 43.813 31.128 44.483 ;
     RECT  34.8 44.149 37.176 44.483 ;
     RECT  47.088 43.955 47.112 44.483 ;
     RECT  23.904 44.099 24.312 44.627 ;
     RECT  28.176 44.243 28.2 44.915 ;
     RECT  34.8 44.483 36.312 44.915 ;
     RECT  45.6 43.861 46.008 44.963 ;
     RECT  34.8 44.915 35.88 45.011 ;
     RECT  39.888 44.195 40.512 45.011 ;
     RECT  15.36 43.813 15.384 45.059 ;
     RECT  19.968 43.763 19.992 45.059 ;
     RECT  2.4 37.715 2.712 45.369 ;
     RECT  7.8 42.323 8.112 45.369 ;
     RECT  13.2 38.003 13.512 45.369 ;
     RECT  18.6 44.483 18.912 45.369 ;
     RECT  24 44.627 24.312 45.369 ;
     RECT  29.4 44.243 29.712 45.369 ;
     RECT  34.8 45.011 35.112 45.369 ;
     RECT  40.2 45.011 40.512 45.369 ;
     RECT  45.6 44.963 45.912 45.369 ;
     RECT  2.4 45.369 2.52 45.383 ;
     RECT  7.8 45.369 7.92 45.383 ;
     RECT  13.2 45.369 13.32 45.383 ;
     RECT  18.6 45.369 18.72 45.383 ;
     RECT  24 45.369 24.12 45.383 ;
     RECT  29.4 45.369 29.52 45.383 ;
     RECT  34.8 45.369 34.92 45.383 ;
     RECT  40.2 45.369 40.32 45.383 ;
     RECT  45.6 45.369 45.72 45.383 ;
     RECT  30.072 2.629 31.296 2.821 ;
     RECT  45.912 2.629 47.136 4.019 ;
     RECT  40.512 2.773 41.568 3.683 ;
     RECT  13.512 2.821 14.496 4.645 ;
     RECT  14.52 2.821 15.84 3.683 ;
     RECT  11.448 3.013 12.816 3.875 ;
     RECT  37.464 3.397 38.784 3.971 ;
     RECT  38.808 3.397 40.2 3.685 ;
     RECT  30.792 3.443 30.84 4.259 ;
     RECT  23.328 3.635 23.904 3.683 ;
     RECT  14.52 3.683 15.864 4.549 ;
     RECT  23.328 3.683 24 4.501 ;
     RECT  38.808 3.685 40.08 3.971 ;
     RECT  2.856 3.925 4.368 4.595 ;
     RECT  45.912 4.019 46.008 4.501 ;
     RECT  29.832 4.259 30.84 4.885 ;
     RECT  22.776 4.501 24 5.461 ;
     RECT  14.52 4.549 15.984 5.315 ;
     RECT  2.712 4.595 4.368 5.221 ;
     RECT  29.832 4.885 30.816 5.171 ;
     RECT  2.712 5.221 4.224 7.621 ;
     RECT  22.776 5.461 23.904 6.947 ;
     RECT  26.784 5.699 26.808 6.229 ;
     RECT  7.392 6.035 7.488 6.851 ;
     RECT  21.192 6.229 22.704 7.429 ;
     RECT  26.568 6.229 26.808 6.709 ;
     RECT  39 6.229 40.032 6.899 ;
     RECT  26.568 6.709 27.648 7.379 ;
     RECT  7.392 6.851 7.8 7.381 ;
     RECT  38.976 6.899 40.032 7.381 ;
     RECT  22.776 6.947 24 11.171 ;
     RECT  27.672 6.949 29.088 7.619 ;
     RECT  32.52 7.189 33.504 8.675 ;
     RECT  33.528 7.235 34.8 8.675 ;
     RECT  6.792 7.381 7.8 9.155 ;
     RECT  38.76 7.381 40.032 8.003 ;
     RECT  45.12 7.427 45.168 8.485 ;
     RECT  21.192 7.429 22.176 7.909 ;
     RECT  27.888 7.619 29.088 8.339 ;
     RECT  2.712 7.621 4.032 8.723 ;
     RECT  35.208 7.861 36.624 9.685 ;
     RECT  39.888 8.003 40.032 8.677 ;
     RECT  47.952 8.243 47.976 9.637 ;
     RECT  27.888 8.339 29.4 8.485 ;
     RECT  27.912 8.485 29.4 10.067 ;
     RECT  34.176 8.675 34.8 9.061 ;
     RECT  2.712 8.723 4.512 8.821 ;
     RECT  3.096 8.821 4.512 9.011 ;
     RECT  25.128 8.917 26.16 9.251 ;
     RECT  11.448 9.061 12.624 9.155 ;
     RECT  12.528 9.155 12.624 9.925 ;
     RECT  24.888 9.251 26.16 10.883 ;
     RECT  35.208 9.685 36.48 9.923 ;
     RECT  36.648 9.685 37.68 9.877 ;
     RECT  35.112 9.923 36.48 10.595 ;
     RECT  18.912 10.067 19.032 11.125 ;
     RECT  17.304 10.261 18.6 12.421 ;
     RECT  34.176 10.595 34.8 11.269 ;
     RECT  35.112 10.595 35.352 11.941 ;
     RECT  24.888 10.883 26.136 11.029 ;
     RECT  24.888 11.029 26.112 12.563 ;
     RECT  22.728 11.171 24 12.131 ;
     RECT  6.456 11.173 7.8 12.515 ;
     RECT  8.568 11.173 9.648 13.765 ;
     RECT  32.52 11.269 33.504 12.755 ;
     RECT  33.528 11.269 34.8 11.845 ;
     RECT  37.512 11.459 37.56 12.469 ;
     RECT  33.672 11.845 34.8 13.235 ;
     RECT  22.2 12.131 24 13.045 ;
     RECT  17.304 12.421 18.48 12.611 ;
     RECT  24.888 12.563 26.136 13.093 ;
     RECT  17.304 12.611 18.6 12.755 ;
     RECT  18.48 12.755 18.6 13.909 ;
     RECT  10.344 12.853 11.712 13.283 ;
     RECT  11.736 12.853 13.2 13.331 ;
     RECT  22.2 13.045 23.376 14.339 ;
     RECT  24.888 13.093 26.736 13.477 ;
     RECT  11.424 13.283 11.712 13.285 ;
     RECT  25.656 13.477 26.736 14.677 ;
     RECT  2.712 13.811 3.984 17.315 ;
     RECT  19.704 13.861 20.688 13.955 ;
     RECT  20.712 13.907 22.176 14.963 ;
     RECT  20.592 13.955 20.688 15.157 ;
     RECT  8.808 14.099 9.672 14.915 ;
     RECT  16.56 14.387 16.584 15.637 ;
     RECT  4.104 14.531 5.088 14.867 ;
     RECT  26.376 14.723 27.696 14.819 ;
     RECT  33.672 14.773 34.8 16.595 ;
     RECT  8.472 14.915 9.672 15.253 ;
     RECT  20.712 14.963 21.72 16.213 ;
     RECT  44.88 15.059 45.024 15.829 ;
     RECT  8.472 15.253 9.888 16.019 ;
     RECT  24.888 15.491 26.352 20.485 ;
     RECT  42.216 15.829 43.584 16.019 ;
     RECT  43.608 15.829 45.024 16.595 ;
     RECT  21.672 16.213 21.72 16.405 ;
     RECT  19.416 16.453 20.592 17.363 ;
     RECT  13.512 16.501 14.832 17.123 ;
     RECT  33.84 16.595 34.8 17.173 ;
     RECT  17.112 16.597 18.6 17.651 ;
     RECT  28.392 16.885 29.4 18.565 ;
     RECT  21.72 17.029 22.8 19.237 ;
     RECT  22.824 17.029 24 17.317 ;
     RECT  20.616 17.171 21.648 17.363 ;
     RECT  2.712 17.315 4.08 19.333 ;
     RECT  22.824 17.317 23.904 17.459 ;
     RECT  19.416 17.363 19.704 17.941 ;
     RECT  22.824 17.459 24 19.523 ;
     RECT  43.944 18.181 45.024 18.803 ;
     RECT  13.512 18.757 14.688 20.339 ;
     RECT  43.92 18.803 45.024 19.621 ;
     RECT  20.424 19.237 21.648 19.283 ;
     RECT  20.424 19.283 21.696 20.051 ;
     RECT  2.952 19.333 4.08 19.811 ;
     RECT  22.104 19.523 24 19.909 ;
     RECT  43.656 19.621 45.024 20.627 ;
     RECT  2.712 19.811 4.08 20.291 ;
     RECT  39.144 19.811 40.2 20.579 ;
     RECT  22.104 19.909 23.424 20.579 ;
     RECT  29.712 19.909 30.72 20.867 ;
     RECT  12.12 19.955 13.2 22.307 ;
     RECT  2.712 20.291 3.96 21.061 ;
     RECT  13.512 20.339 14.736 21.637 ;
     RECT  17.112 20.485 18.6 21.155 ;
     RECT  25.128 20.485 26.352 21.971 ;
     RECT  27.336 20.485 28.368 21.155 ;
     RECT  45.216 20.627 45.6 22.021 ;
     RECT  29.712 20.867 30.552 21.541 ;
     RECT  2.712 21.061 3.936 22.165 ;
     RECT  26.376 21.155 28.368 22.645 ;
     RECT  33.84 21.155 34.8 21.301 ;
     RECT  32.52 21.301 34.8 22.213 ;
     RECT  28.392 21.395 29.4 22.835 ;
     RECT  13.512 21.637 14.64 22.739 ;
     RECT  21.696 21.683 22.08 22.741 ;
     RECT  24.888 21.971 26.352 23.411 ;
     RECT  32.52 22.213 33.648 22.741 ;
     RECT  33.672 22.213 34.704 22.787 ;
     RECT  11.256 22.307 13.2 23.171 ;
     RECT  40.512 22.451 40.632 22.741 ;
     RECT  27.336 22.645 28.368 22.835 ;
     RECT  13.512 22.739 14.784 23.555 ;
     RECT  40.512 22.741 41.568 23.941 ;
     RECT  29.136 22.835 29.4 22.981 ;
     RECT  12.768 23.171 13.2 23.317 ;
     RECT  13.512 23.555 14.232 23.893 ;
     RECT  8.112 23.989 9.12 24.131 ;
     RECT  40.512 24.419 41.568 24.515 ;
     RECT  12.768 24.467 13.2 25.573 ;
     RECT  29.712 24.755 30.552 25.189 ;
     RECT  29.712 25.189 30.72 26.723 ;
     RECT  32.376 25.237 33.648 27.109 ;
     RECT  33.672 25.237 34.8 26.437 ;
     RECT  11.064 25.621 12.576 26.387 ;
     RECT  13.512 25.715 14.592 26.531 ;
     RECT  30.744 25.765 32.208 26.723 ;
     RECT  38.088 26.003 39.072 26.579 ;
     RECT  14.616 26.197 15.936 26.531 ;
     RECT  24.312 26.197 25.488 27.347 ;
     RECT  13.512 26.531 15.936 26.677 ;
     RECT  38.088 26.579 39.312 27.203 ;
     RECT  13.896 26.677 15.936 26.771 ;
     RECT  13.896 26.771 14.856 27.877 ;
     RECT  2.712 26.819 3.936 27.203 ;
     RECT  36.84 26.869 38.064 27.013 ;
     RECT  32.472 27.109 33.648 27.635 ;
     RECT  2.712 27.203 3.672 28.453 ;
     RECT  42.504 27.301 43.92 28.547 ;
     RECT  32.472 27.635 34.176 27.923 ;
     RECT  27.96 27.877 29.4 28.499 ;
     RECT  13.512 27.923 14.832 29.411 ;
     RECT  32.472 27.923 34.464 28.163 ;
     RECT  33.552 28.163 34.464 29.029 ;
     RECT  27.936 28.499 29.4 29.509 ;
     RECT  42.72 28.547 43.92 29.365 ;
     RECT  22.776 28.789 24 29.411 ;
     RECT  18.912 29.075 19.032 29.605 ;
     RECT  42.744 29.365 43.92 30.035 ;
     RECT  13.512 29.411 14.928 30.083 ;
     RECT  26.376 29.509 27.888 30.275 ;
     RECT  27.912 29.509 29.4 30.275 ;
     RECT  18.912 29.605 19.92 30.565 ;
     RECT  42.744 30.035 44.016 30.851 ;
     RECT  28.848 30.275 29.4 31.237 ;
     RECT  29.712 30.421 30.96 31.379 ;
     RECT  44.328 30.709 45.6 31.477 ;
     RECT  42.744 30.851 44.064 32.243 ;
     RECT  17.352 30.949 18.6 33.059 ;
     RECT  25.08 30.949 26.352 32.915 ;
     RECT  29.712 31.379 31.872 32.437 ;
     RECT  44.568 31.477 45.6 33.971 ;
     RECT  8.112 31.765 9.168 34.741 ;
     RECT  7.584 31.811 7.8 32.917 ;
     RECT  29.712 32.437 30.816 33.253 ;
     RECT  30.84 32.437 31.872 33.299 ;
     RECT  40.512 32.483 41.064 33.013 ;
     RECT  22.776 32.773 24 37.091 ;
     RECT  6.648 32.917 7.8 34.499 ;
     RECT  40.512 33.013 42.144 33.731 ;
     RECT  40.512 33.731 41.016 33.925 ;
     RECT  44.424 33.971 45.6 35.171 ;
     RECT  31.896 34.405 33.216 34.835 ;
     RECT  33.24 34.405 34.464 34.835 ;
     RECT  7.68 34.499 7.8 35.269 ;
     RECT  24.312 34.741 25.296 36.275 ;
     RECT  25.32 34.741 26.352 35.027 ;
     RECT  33.24 34.835 34.512 35.027 ;
     RECT  8.112 35.027 9.168 37.909 ;
     RECT  44.184 35.171 45.6 36.421 ;
     RECT  12.024 35.269 13.2 35.939 ;
     RECT  45.912 36.227 47.184 36.515 ;
     RECT  44.184 36.421 45.504 38.819 ;
     RECT  45.912 36.515 47.208 36.613 ;
     RECT  45.912 36.613 47.232 38.005 ;
     RECT  17.112 36.949 18.6 37.091 ;
     RECT  15.48 37.573 16.992 38.723 ;
     RECT  47.256 37.573 48.576 38.723 ;
     RECT  8.112 37.909 9.12 39.107 ;
     RECT  13.512 38.003 13.608 38.965 ;
     RECT  45.912 38.005 46.944 38.723 ;
     RECT  23.016 38.677 24 40.019 ;
     RECT  41.016 38.677 42.528 39.395 ;
     RECT  45.912 38.723 47.232 39.829 ;
     RECT  5.496 38.725 6.96 38.867 ;
     RECT  44.184 38.819 45.6 42.851 ;
     RECT  13.512 38.965 14.784 40.451 ;
     RECT  17.016 39.205 18.48 39.251 ;
     RECT  46.008 39.829 47.232 41.363 ;
     RECT  47.256 40.981 48.288 41.699 ;
     RECT  45.912 41.363 47.232 41.653 ;
     RECT  45.912 41.653 47.088 43.861 ;
     RECT  47.112 41.699 48.288 42.803 ;
     RECT  28.848 42.227 29.4 43.669 ;
     RECT  18.912 42.661 20.16 43.717 ;
     RECT  47.112 42.803 47.592 43.141 ;
     RECT  41.016 42.997 42.24 44.099 ;
     RECT  18.912 43.717 19.968 45.059 ;
     RECT  29.712 43.813 31.104 44.483 ;
     RECT  35.88 43.813 37.152 44.149 ;
     RECT  46.008 43.861 47.088 44.483 ;
     RECT  28.2 44.243 29.4 44.915 ;
  END
END ot_s81sl_cap_ed
END LIBRARY
